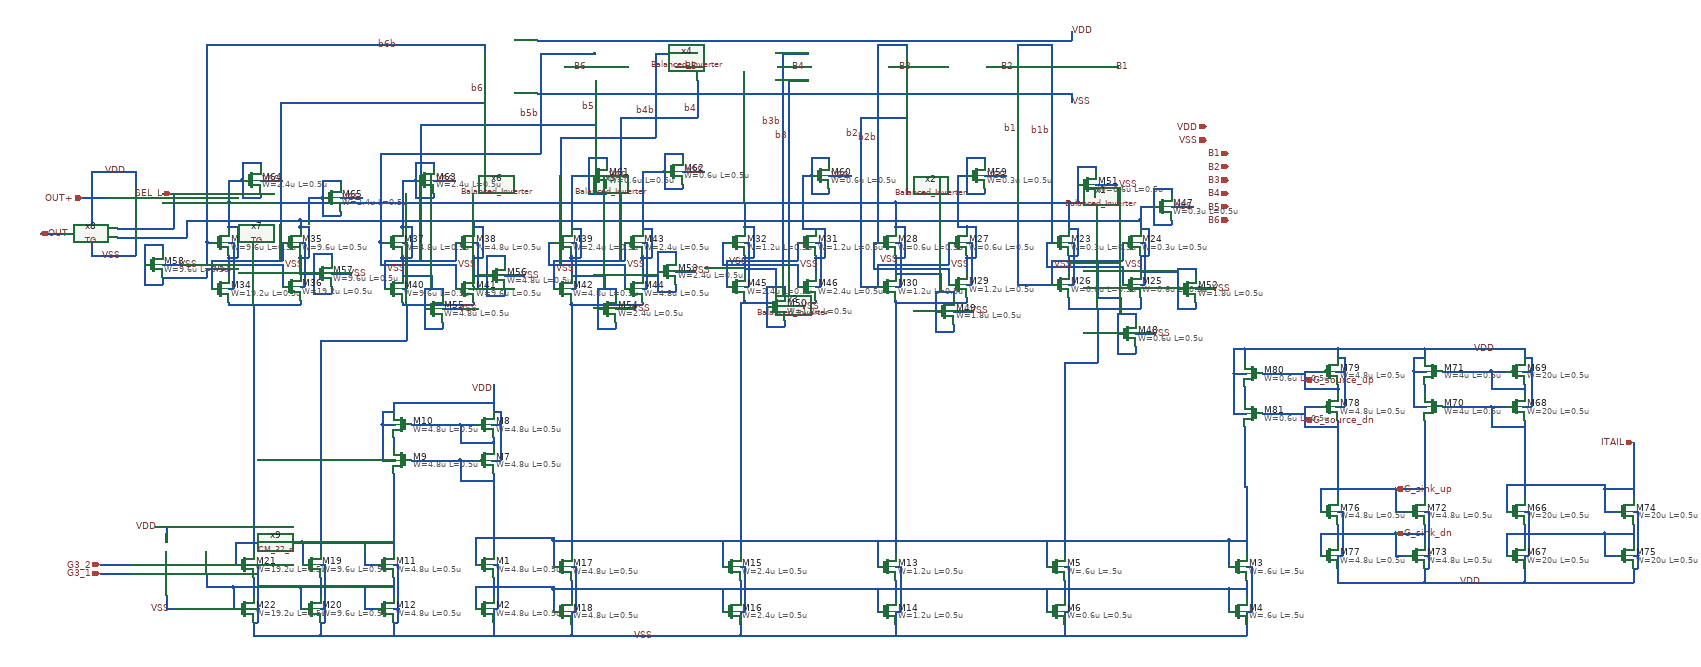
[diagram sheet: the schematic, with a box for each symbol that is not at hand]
v {xschem version=3.1.0 file_version=1.2
}
G {}
K {}
V {}
S {}
E {}
N 1940 -170 1950 -170 {
lab=VSS}
N 1950 -170 1950 -70 {
lab=VSS}
N 1940 -70 1950 -70 {
lab=VSS}
N 2350 -170 2360 -170 {
lab=VSS}
N 2360 -170 2360 -70 {
lab=VSS}
N 2350 -70 2360 -70 {
lab=VSS}
N 2310 -230 2310 -170 {
lab=#net1}
N 2310 -230 2350 -230 {
lab=#net1}
N 2310 -120 2310 -70 {
lab=#net2}
N 1940 -15 2350 -15 {
lab=VSS}
N 1560 -15 1940 -15 {
lab=VSS}
N 1210 -15 1560 -15 {
lab=VSS}
N 830 -15 1210 -15 {
lab=VSS}
N 1560 -170 1570 -170 {
lab=VSS}
N 1570 -170 1570 -70 {
lab=VSS}
N 1560 -70 1570 -70 {
lab=VSS}
N 1210 -170 1220 -170 {
lab=VSS}
N 1220 -170 1220 -70 {
lab=VSS}
N 1210 -70 1220 -70 {
lab=VSS}
N 830 -170 840 -170 {
lab=VSS}
N 840 -170 840 -70 {
lab=VSS}
N 830 -70 840 -70 {
lab=VSS}
N 1900 -230 1900 -170 {
lab=#net1}
N 1900 -120 1900 -70 {
lab=#net2}
N 1520 -230 1520 -170 {
lab=#net1}
N 1520 -120 1520 -70 {
lab=#net2}
N 1170 -230 1170 -170 {
lab=#net1}
N 1170 -120 1170 -70 {
lab=#net2}
N 790 -230 790 -170 {
lab=#net1}
N 790 -120 790 -70 {
lab=#net2}
N 2310 -120 2350 -120 {
lab=#net2}
N 2350 -270 2350 -205 {
lab=#net1}
N 2350 -70 2350 -30 {
lab=VSS}
N 1940 -70 1940 -35 {
lab=VSS}
N 1940 -35 1940 -30 {
lab=VSS}
N 1940 -30 1940 -15 {
lab=VSS}
N 2350 -30 2350 -15 {
lab=VSS}
N 1940 -135 1940 -105 {
lab=#net3}
N 2350 -135 2350 -105 {
lab=#net2}
N 1560 -135 1560 -105 {
lab=#net4}
N 1210 -135 1210 -105 {
lab=#net5}
N 830 -135 830 -105 {
lab=#net6}
N 2350 -205 2350 -200 {
lab=#net1}
N 2350 -140 2350 -135 {
lab=#net2}
N 2350 -105 2350 -100 {
lab=#net2}
N 1560 -205 1560 -200 {
lab=#net7}
N 1560 -140 1560 -135 {
lab=#net4}
N 1560 -105 1560 -100 {
lab=#net4}
N 1210 -205 1210 -200 {
lab=#net8}
N 1210 -140 1210 -135 {
lab=#net5}
N 1210 -105 1210 -100 {
lab=#net5}
N 830 -140 830 -135 {
lab=#net6}
N 830 -105 830 -100 {
lab=#net6}
N 830 -70 830 -15 {
lab=VSS}
N 1210 -70 1210 -15 {
lab=VSS}
N 1560 -70 1560 -15 {
lab=VSS}
N 1940 -140 1940 -135 {
lab=#net3}
N 1940 -105 1940 -100 {
lab=#net3}
N 790 -120 2310 -120 {
lab=#net2}
N 790 -230 2310 -230 {
lab=#net1}
N 830 -210 830 -200 {
lab=#net9}
N 655 -175 665 -175 {
lab=VSS}
N 665 -175 665 -75 {
lab=VSS}
N 655 -75 665 -75 {
lab=VSS}
N 615 -235 615 -175 {
lab=#net1}
N 615 -125 615 -75 {
lab=#net2}
N 655 -140 655 -110 {
lab=#net10}
N 655 -145 655 -140 {
lab=#net10}
N 655 -110 655 -105 {
lab=#net10}
N 655 -75 655 -20 {
lab=VSS}
N 655 -215 655 -205 {
lab=#net11}
N 655 -20 655 -15 {
lab=VSS}
N 655 -15 830 -15 {
lab=VSS}
N 790 -235 790 -230 {
lab=#net1}
N 615 -125 790 -125 {
lab=#net2}
N 790 -125 790 -120 {
lab=#net2}
N 830 -285 830 -210 {
lab=#net9}
N 1940 -295 1940 -200 {
lab=#net12}
N 1560 -210 1560 -205 {
lab=#net7}
N 1560 -320 1560 -210 {
lab=#net7}
N 1210 -345 1210 -205 {
lab=#net8}
N 655 -380 655 -215 {
lab=#net11}
N 615 -235 790 -235 {
lab=#net1}
N 580 -490 615 -490 {
lab=#net13}
N 580 -490 580 -450 {
lab=#net13}
N 580 -450 655 -450 {
lab=#net13}
N 655 -460 655 -450 {
lab=#net13}
N 655 -450 655 -440 {
lab=#net13}
N 650 -410 670 -410 {
lab=VDD}
N 670 -490 670 -410 {
lab=VDD}
N 650 -490 670 -490 {
lab=VDD}
N 670 -520 670 -490 {
lab=VDD}
N 655 -520 670 -520 {
lab=VDD}
N 655 -580 655 -520 {
lab=VDD}
N 580 -410 615 -410 {
lab=#net11}
N 580 -410 580 -365 {
lab=#net11}
N 580 -365 655 -365 {
lab=#net11}
N 470 -490 580 -490 {
lab=#net13}
N 470 -410 580 -410 {
lab=#net11}
N 430 -460 430 -440 {
lab=#net14}
N 430 -540 430 -520 {
lab=VDD}
N 430 -540 655 -540 {
lab=VDD}
N 430 -380 430 -305 {
lab=#net15}
N 405 -410 435 -410 {
lab=VDD}
N 405 -490 405 -410 {
lab=VDD}
N 405 -490 435 -490 {
lab=VDD}
N 405 -490 435 -490 {
lab=VDD}
N 405 -520 405 -490 {
lab=VDD}
N 405 -520 430 -520 {
lab=VDD}
N 430 -305 430 -205 {
lab=#net15}
N 430 -145 430 -105 {
lab=#net16}
N 430 -175 440 -175 {
lab=VSS}
N 440 -175 440 -75 {
lab=VSS}
N 430 -75 440 -75 {
lab=VSS}
N 430 -75 440 -75 {
lab=VSS}
N 440 -75 440 -45 {
lab=VSS}
N 430 -45 440 -45 {
lab=VSS}
N 430 -45 430 -15 {
lab=VSS}
N 430 -15 655 -15 {
lab=VSS}
N 265 -145 265 -105 {
lab=#net17}
N 265 -175 275 -175 {
lab=VSS}
N 275 -175 275 -75 {
lab=VSS}
N 265 -75 275 -75 {
lab=VSS}
N 265 -75 275 -75 {
lab=VSS}
N 275 -75 275 -45 {
lab=VSS}
N 265 -45 275 -45 {
lab=VSS}
N 265 -45 265 -15 {
lab=VSS}
N 225 -225 225 -175 {
lab=#net15}
N 225 -225 430 -225 {
lab=#net15}
N 365 -175 390 -175 {
lab=#net15}
N 365 -225 365 -175 {
lab=#net15}
N 365 -125 430 -125 {
lab=#net16}
N 365 -125 365 -75 {
lab=#net16}
N 365 -75 390 -75 {
lab=#net16}
N 220 -125 365 -125 {
lab=#net16}
N 220 -125 220 -75 {
lab=#net16}
N 220 -75 225 -75 {
lab=#net16}
N 265 -15 430 -15 {
lab=VSS}
N 265 -290 265 -205 {
lab=#net18}
N 115 -145 115 -105 {
lab=#net19}
N 115 -175 125 -175 {
lab=VSS}
N 125 -175 125 -75 {
lab=VSS}
N 115 -75 125 -75 {
lab=VSS}
N 115 -75 125 -75 {
lab=VSS}
N 125 -75 125 -45 {
lab=VSS}
N 115 -45 125 -45 {
lab=VSS}
N 115 -45 115 -15 {
lab=VSS}
N 75 -225 75 -175 {
lab=#net15}
N 70 -125 70 -75 {
lab=#net16}
N 70 -75 75 -75 {
lab=#net16}
N 115 -290 115 -205 {
lab=#net20}
N 70 -125 220 -125 {
lab=#net16}
N 75 -225 225 -225 {
lab=#net15}
N 115 -15 265 -15 {
lab=VSS}
N 2015 -1295 2055 -1295 {
lab=B1}
N 1705 -1355 1955 -1355 {
lab=VDD}
N 1485 -1355 1705 -1355 {
lab=VDD}
N 1235 -1355 1485 -1355 {
lab=VDD}
N 1005 -1355 1235 -1355 {
lab=VDD}
N 755 -1355 1005 -1355 {
lab=VDD}
N 755 -1235 1005 -1235 {
lab=VSS}
N 1005 -1235 1235 -1235 {
lab=VSS}
N 1235 -1235 1485 -1235 {
lab=VSS}
N 1485 -1235 1705 -1235 {
lab=VSS}
N 1705 -1235 1955 -1235 {
lab=VSS}
N 1835 -1345 1835 -1325 {
lab=b1b}
N 1835 -1265 1835 -1245 {
lab=b1}
N 1765 -1295 1795 -1295 {
lab=B2}
N 1545 -1295 1565 -1295 {
lab=B3}
N 1295 -1295 1325 -1295 {
lab=B4}
N 1065 -1295 1085 -1295 {
lab=B5}
N 885 -1265 885 -1245 {
lab=b5}
N 815 -1295 835 -1295 {
lab=B6}
N 635 -1345 635 -1325 {
lab=b6b}
N 635 -1265 635 -1245 {
lab=b6}
N 60 -990 1560 -990 {
lab=#net21}
N 1560 -990 1950 -990 {
lab=#net21}
N 1950 -990 1950 -930 {
lab=#net21}
N 2110 -950 2110 -930 {
lab=#net22}
N 180 -900 180 -860 {
lab=b6}
N 20 -860 180 -860 {
lab=b6}
N 20 -860 20 -800 {
lab=b6}
N 10 -900 20 -900 {
lab=b6b}
N 10 -900 10 -850 {
lab=b6b}
N 10 -850 180 -850 {
lab=b6b}
N 180 -850 180 -800 {
lab=b6b}
N 60 -900 70 -900 {
lab=VSS}
N 70 -900 70 -800 {
lab=VSS}
N 220 -900 230 -900 {
lab=VSS}
N 230 -900 230 -800 {
lab=VSS}
N 220 -800 230 -800 {
lab=VSS}
N 450 -900 460 -900 {
lab=VSS}
N 460 -900 460 -800 {
lab=VSS}
N 610 -900 620 -900 {
lab=VSS}
N 620 -900 620 -800 {
lab=VSS}
N 400 -900 410 -900 {
lab=b5b}
N 400 -900 400 -850 {
lab=b5b}
N 400 -850 570 -850 {
lab=b5b}
N 570 -850 570 -800 {
lab=b5b}
N 570 -900 570 -860 {
lab=b5}
N 410 -860 570 -860 {
lab=b5}
N 410 -860 410 -800 {
lab=b5}
N 780 -900 780 -850 {
lab=b4b}
N 780 -850 950 -850 {
lab=b4b}
N 950 -850 950 -800 {
lab=b4b}
N 790 -860 790 -800 {
lab=b4}
N 790 -860 950 -860 {
lab=b4}
N 950 -900 950 -860 {
lab=b4}
N 1220 -900 1230 -900 {
lab=VSS}
N 1230 -900 1230 -800 {
lab=VSS}
N 1220 -800 1230 -800 {
lab=VSS}
N 1380 -900 1390 -900 {
lab=VSS}
N 1390 -900 1390 -800 {
lab=VSS}
N 1380 -800 1390 -800 {
lab=VSS}
N 1560 -900 1570 -900 {
lab=VSS}
N 1570 -900 1570 -800 {
lab=VSS}
N 1560 -800 1570 -800 {
lab=VSS}
N 1720 -900 1730 -900 {
lab=VSS}
N 830 -760 990 -760 {
lab=#net9}
N 1220 -765 1380 -765 {
lab=#net8}
N 1170 -900 1180 -900 {
lab=b3b}
N 1170 -900 1170 -850 {
lab=b3b}
N 1170 -850 1340 -850 {
lab=b3b}
N 1340 -850 1340 -800 {
lab=b3b}
N 1340 -900 1340 -860 {
lab=b3}
N 1180 -860 1340 -860 {
lab=b3}
N 1180 -860 1180 -800 {
lab=b3}
N 1510 -900 1520 -900 {
lab=b2b}
N 1510 -900 1510 -840 {
lab=b2b}
N 1510 -840 1680 -840 {
lab=b2b}
N 1680 -900 1680 -850 {
lab=b2}
N 1520 -850 1680 -850 {
lab=b2}
N 1520 -850 1520 -800 {
lab=b2}
N 1950 -900 1960 -900 {
lab=VSS}
N 2110 -900 2120 -900 {
lab=VSS}
N 2070 -900 2070 -860 {
lab=b1}
N 1910 -860 2070 -860 {
lab=b1}
N 1900 -900 1910 -900 {
lab=b1b}
N 1900 -845 2070 -845 {
lab=b1b}
N 1210 -765 1220 -765 {
lab=#net8}
N 1955 -1375 1955 -1355 {
lab=VDD}
N 1955 -1235 1955 -1215 {
lab=VSS}
N 830 -900 840 -900 {
lab=VSS}
N 840 -900 840 -800 {
lab=VSS}
N 990 -900 1000 -900 {
lab=VSS}
N 1000 -900 1000 -800 {
lab=VSS}
N 80 -930 80 -870 {
lab=#net21}
N 220 -935 240 -935 {
lab=#net22}
N 240 -930 240 -870 {
lab=#net22}
N 470 -930 470 -870 {
lab=#net21}
N 630 -930 630 -870 {
lab=#net22}
N 850 -930 850 -870 {
lab=#net21}
N 1010 -930 1010 -870 {
lab=#net22}
N 1240 -930 1240 -870 {
lab=#net21}
N 1400 -930 1400 -870 {
lab=#net22}
N 1580 -930 1580 -870 {
lab=#net21}
N 1740 -930 1740 -870 {
lab=#net22}
N 1950 -930 1970 -930 {
lab=#net21}
N 1970 -930 1970 -870 {
lab=#net21}
N 1950 -870 1970 -870 {
lab=#net21}
N 2110 -930 2130 -930 {
lab=#net22}
N 2130 -930 2130 -870 {
lab=#net22}
N 2110 -870 2130 -870 {
lab=#net22}
N 1500 -800 1520 -800 {
lab=b2}
N 2070 -840 2070 -805 {
lab=b1b}
N 2120 -900 2120 -805 {
lab=VSS}
N 2110 -870 2110 -840 {
lab=#net22}
N 1950 -870 1950 -840 {
lab=#net21}
N 1960 -900 1960 -805 {
lab=VSS}
N 1950 -805 1960 -805 {
lab=VSS}
N 2070 -845 2070 -840 {
lab=b1b}
N 1910 -860 1910 -805 {
lab=b1}
N 1850 -805 1910 -805 {
lab=b1}
N 1720 -935 1740 -935 {
lab=#net22}
N 1740 -935 1740 -930 {
lab=#net22}
N 1720 -865 1740 -865 {
lab=#net22}
N 1740 -870 1740 -865 {
lab=#net22}
N 1560 -990 1560 -935 {
lab=#net21}
N 1560 -935 1580 -935 {
lab=#net21}
N 1580 -935 1580 -930 {
lab=#net21}
N 1560 -865 1580 -865 {
lab=#net21}
N 1580 -870 1580 -865 {
lab=#net21}
N 1720 -865 1720 -840 {
lab=#net22}
N 1730 -900 1730 -805 {
lab=VSS}
N 1720 -805 1730 -805 {
lab=VSS}
N 1680 -840 1680 -805 {
lab=b2b}
N 1560 -765 1720 -765 {
lab=#net7}
N 1720 -770 1720 -765 {
lab=#net7}
N 1560 -865 1560 -835 {
lab=#net21}
N 1380 -865 1400 -865 {
lab=#net22}
N 1400 -870 1400 -865 {
lab=#net22}
N 1220 -990 1220 -935 {
lab=#net21}
N 1240 -935 1240 -930 {
lab=#net21}
N 1220 -935 1240 -935 {
lab=#net21}
N 1220 -865 1240 -865 {
lab=#net21}
N 1240 -870 1240 -865 {
lab=#net21}
N 1380 -865 1380 -835 {
lab=#net22}
N 1220 -865 1220 -835 {
lab=#net21}
N 990 -865 990 -830 {
lab=#net22}
N 990 -865 1010 -865 {
lab=#net22}
N 1010 -870 1010 -865 {
lab=#net22}
N 990 -950 990 -935 {
lab=#net22}
N 780 -900 790 -900 {
lab=b4b}
N 830 -865 850 -865 {
lab=#net21}
N 850 -870 850 -865 {
lab=#net21}
N 830 -865 830 -830 {
lab=#net21}
N 990 -795 1000 -795 {
lab=VSS}
N 1000 -800 1000 -795 {
lab=VSS}
N 790 -800 790 -795 {
lab=b4}
N 950 -800 950 -795 {
lab=b4b}
N 830 -795 840 -795 {
lab=VSS}
N 840 -800 840 -795 {
lab=VSS}
N 610 -950 610 -935 {
lab=#net22}
N 610 -935 630 -935 {
lab=#net22}
N 630 -935 630 -930 {
lab=#net22}
N 610 -865 630 -865 {
lab=#net22}
N 630 -870 630 -865 {
lab=#net22}
N 610 -865 610 -830 {
lab=#net22}
N 450 -990 450 -935 {
lab=#net21}
N 450 -865 450 -830 {
lab=#net21}
N 470 -870 470 -865 {
lab=#net21}
N 450 -865 470 -865 {
lab=#net21}
N 470 -935 470 -930 {
lab=#net21}
N 450 -935 470 -935 {
lab=#net21}
N 620 -800 620 -795 {
lab=VSS}
N 610 -795 620 -795 {
lab=VSS}
N 570 -800 570 -795 {
lab=b5b}
N 450 -795 460 -795 {
lab=VSS}
N 460 -800 460 -795 {
lab=VSS}
N 410 -800 410 -795 {
lab=b5}
N 450 -760 610 -760 {
lab=#net18}
N 220 -950 220 -935 {
lab=#net22}
N 240 -935 240 -930 {
lab=#net22}
N 220 -865 240 -865 {
lab=#net22}
N 240 -870 240 -865 {
lab=#net22}
N 220 -865 220 -830 {
lab=#net22}
N 60 -990 60 -935 {
lab=#net21}
N 60 -935 80 -935 {
lab=#net21}
N 80 -935 80 -930 {
lab=#net21}
N 60 -865 80 -865 {
lab=#net21}
N 80 -870 80 -865 {
lab=#net21}
N 60 -865 60 -830 {
lab=#net21}
N 60 -760 220 -760 {
lab=#net20}
N 220 -765 220 -760 {
lab=#net20}
N 20 -800 20 -795 {
lab=b6}
N 60 -795 70 -795 {
lab=VSS}
N 70 -800 70 -795 {
lab=VSS}
N 2110 -805 2120 -805 {
lab=VSS}
N 2110 -840 2110 -835 {
lab=#net22}
N 1950 -840 1950 -835 {
lab=#net21}
N 1720 -935 1720 -930 {
lab=#net22}
N 1560 -935 1560 -930 {
lab=#net21}
N 1720 -870 1720 -865 {
lab=#net22}
N 1560 -870 1560 -865 {
lab=#net21}
N 1720 -840 1720 -835 {
lab=#net22}
N 1720 -775 1720 -770 {
lab=#net7}
N 1560 -835 1560 -830 {
lab=#net21}
N 1560 -770 1560 -765 {
lab=#net7}
N 1380 -870 1380 -865 {
lab=#net22}
N 1220 -935 1220 -930 {
lab=#net21}
N 1220 -870 1220 -865 {
lab=#net21}
N 60 -935 60 -930 {
lab=#net21}
N 60 -870 60 -865 {
lab=#net21}
N 60 -830 60 -825 {
lab=#net21}
N 60 -765 60 -760 {
lab=#net20}
N 220 -935 220 -930 {
lab=#net22}
N 220 -870 220 -865 {
lab=#net22}
N 220 -835 220 -830 {
lab=#net22}
N 220 -770 220 -765 {
lab=#net20}
N 450 -935 450 -930 {
lab=#net21}
N 450 -870 450 -865 {
lab=#net21}
N 610 -935 610 -930 {
lab=#net22}
N 610 -870 610 -865 {
lab=#net22}
N 830 -870 830 -865 {
lab=#net21}
N 450 -830 450 -825 {
lab=#net21}
N 450 -765 450 -760 {
lab=#net18}
N 610 -830 610 -825 {
lab=#net22}
N 610 -765 610 -760 {
lab=#net18}
N 830 -830 830 -825 {
lab=#net21}
N 830 -765 830 -760 {
lab=#net9}
N 990 -935 990 -930 {
lab=#net22}
N 990 -870 990 -865 {
lab=#net22}
N 990 -830 990 -825 {
lab=#net22}
N 990 -765 990 -760 {
lab=#net9}
N 1220 -835 1220 -830 {
lab=#net21}
N 1220 -770 1220 -765 {
lab=#net8}
N 1380 -835 1380 -830 {
lab=#net22}
N 1380 -770 1380 -765 {
lab=#net8}
N 1950 -775 1950 -750 {
lab=#net12}
N 1950 -750 2110 -750 {
lab=#net12}
N 2110 -775 2110 -750 {
lab=#net12}
N 2015 -750 2015 -630 {
lab=#net12}
N 1940 -630 2015 -630 {
lab=#net12}
N 2140 -1020 2140 -980 {
lab=#net22}
N 2140 -1020 2180 -1020 {
lab=#net22}
N 2180 -1020 2180 -1010 {
lab=#net22}
N 2180 -950 2180 -940 {
lab=#net22}
N 2140 -940 2180 -940 {
lab=#net22}
N 2140 -980 2140 -940 {
lab=#net22}
N 2180 -980 2230 -980 {
lab=VSS}
N 2110 -980 2110 -950 {
lab=#net22}
N 2110 -980 2140 -980 {
lab=#net22}
N 2060 -740 2060 -695 {
lab=#net21}
N 2060 -740 2100 -740 {
lab=#net21}
N 2100 -740 2100 -725 {
lab=#net21}
N 2060 -695 2060 -650 {
lab=#net21}
N 2060 -650 2100 -650 {
lab=#net21}
N 2100 -665 2100 -650 {
lab=#net21}
N 2100 -695 2145 -695 {
lab=VSS}
N 2065 -775 2065 -740 {
lab=#net21}
N 2015 -775 2065 -775 {
lab=#net21}
N 2015 -855 2015 -775 {
lab=#net21}
N 1950 -855 2015 -855 {
lab=#net21}
N 1650 -790 1650 -745 {
lab=#net21}
N 1650 -790 1690 -790 {
lab=#net21}
N 1690 -790 1690 -775 {
lab=#net21}
N 1650 -745 1650 -700 {
lab=#net21}
N 1650 -700 1690 -700 {
lab=#net21}
N 1690 -715 1690 -700 {
lab=#net21}
N 1690 -745 1735 -745 {
lab=VSS}
N 1560 -830 1660 -830 {
lab=#net21}
N 1660 -830 1660 -790 {
lab=#net21}
N 1270 -800 1270 -755 {
lab=#net21}
N 1270 -800 1310 -800 {
lab=#net21}
N 1310 -800 1310 -785 {
lab=#net21}
N 1270 -755 1270 -710 {
lab=#net21}
N 1270 -710 1310 -710 {
lab=#net21}
N 1310 -725 1310 -710 {
lab=#net21}
N 1310 -755 1355 -755 {
lab=VSS}
N 1220 -840 1290 -840 {
lab=#net21}
N 1290 -840 1290 -800 {
lab=#net21}
N 1970 -1070 1970 -1030 {
lab=#net21}
N 1970 -1070 2010 -1070 {
lab=#net21}
N 2010 -1070 2010 -1060 {
lab=#net21}
N 2010 -1000 2010 -990 {
lab=#net21}
N 1970 -990 2010 -990 {
lab=#net21}
N 1970 -1030 1970 -990 {
lab=#net21}
N 2010 -1030 2060 -1030 {
lab=VSS}
N 1950 -990 1970 -990 {
lab=#net21}
N 2195 -840 2195 -795 {
lab=#net22}
N 2195 -840 2235 -840 {
lab=#net22}
N 2235 -840 2235 -825 {
lab=#net22}
N 2195 -795 2195 -750 {
lab=#net22}
N 2195 -750 2235 -750 {
lab=#net22}
N 2235 -765 2235 -750 {
lab=#net22}
N 2235 -795 2280 -795 {
lab=VSS}
N 2110 -835 2195 -835 {
lab=#net22}
N 1025 -880 1025 -835 {
lab=#net22}
N 1025 -880 1065 -880 {
lab=#net22}
N 1065 -880 1065 -865 {
lab=#net22}
N 1025 -835 1025 -790 {
lab=#net22}
N 1025 -790 1065 -790 {
lab=#net22}
N 1065 -805 1065 -790 {
lab=#net22}
N 1065 -835 1110 -835 {
lab=VSS}
N 990 -825 1025 -825 {
lab=#net22}
N 890 -795 890 -750 {
lab=#net21}
N 890 -795 930 -795 {
lab=#net21}
N 930 -795 930 -780 {
lab=#net21}
N 890 -750 890 -705 {
lab=#net21}
N 890 -705 930 -705 {
lab=#net21}
N 930 -720 930 -705 {
lab=#net21}
N 930 -750 975 -750 {
lab=VSS}
N 830 -825 905 -825 {
lab=#net21}
N 905 -825 905 -795 {
lab=#net21}
N 600 -795 610 -795 {
lab=VSS}
N 610 -800 610 -795 {
lab=VSS}
N 500 -795 500 -750 {
lab=#net21}
N 500 -795 540 -795 {
lab=#net21}
N 540 -795 540 -780 {
lab=#net21}
N 500 -750 500 -705 {
lab=#net21}
N 500 -705 540 -705 {
lab=#net21}
N 540 -720 540 -705 {
lab=#net21}
N 540 -750 585 -750 {
lab=VSS}
N 450 -825 515 -825 {
lab=#net21}
N 515 -825 515 -795 {
lab=#net21}
N 640 -870 640 -825 {
lab=#net22}
N 640 -870 680 -870 {
lab=#net22}
N 680 -870 680 -855 {
lab=#net22}
N 640 -825 640 -780 {
lab=#net22}
N 640 -780 680 -780 {
lab=#net22}
N 680 -795 680 -780 {
lab=#net22}
N 680 -825 725 -825 {
lab=VSS}
N 610 -825 640 -825 {
lab=#net22}
N 250 -875 250 -830 {
lab=#net22}
N 250 -875 290 -875 {
lab=#net22}
N 290 -875 290 -860 {
lab=#net22}
N 250 -830 250 -785 {
lab=#net22}
N 250 -785 290 -785 {
lab=#net22}
N 290 -800 290 -785 {
lab=#net22}
N 290 -830 335 -830 {
lab=VSS}
N 220 -830 250 -830 {
lab=#net22}
N -130 -895 -130 -850 {
lab=#net21}
N -130 -895 -90 -895 {
lab=#net21}
N -90 -895 -90 -880 {
lab=#net21}
N -130 -850 -130 -805 {
lab=#net21}
N -130 -805 -90 -805 {
lab=#net21}
N -90 -820 -90 -805 {
lab=#net21}
N -90 -850 -45 -850 {
lab=VSS}
N -90 -820 10 -820 {
lab=#net21}
N 10 -840 10 -820 {
lab=#net21}
N 10 -840 60 -840 {
lab=#net21}
N 1720 -1090 1720 -1050 {
lab=#net22}
N 1720 -1090 1760 -1090 {
lab=#net22}
N 1760 -1090 1760 -1080 {
lab=#net22}
N 1760 -1020 1760 -1010 {
lab=#net22}
N 1720 -1010 1760 -1010 {
lab=#net22}
N 1720 -1050 1720 -1010 {
lab=#net22}
N 1760 -1050 1810 -1050 {
lab=VSS}
N 1700 -1050 1700 -950 {
lab=#net22}
N 1700 -1050 1720 -1050 {
lab=#net22}
N 1370 -1090 1370 -1050 {
lab=#net22}
N 1370 -1090 1410 -1090 {
lab=#net22}
N 1410 -1090 1410 -1080 {
lab=#net22}
N 1410 -1020 1410 -1010 {
lab=#net22}
N 1370 -1010 1410 -1010 {
lab=#net22}
N 1370 -1050 1370 -1010 {
lab=#net22}
N 1410 -1050 1460 -1050 {
lab=VSS}
N 1350 -1050 1370 -1050 {
lab=#net22}
N 1350 -1050 1350 -950 {
lab=#net22}
N 870 -1090 870 -1050 {
lab=#net21}
N 870 -1090 910 -1090 {
lab=#net21}
N 910 -1090 910 -1080 {
lab=#net21}
N 910 -1020 910 -1010 {
lab=#net21}
N 870 -1010 910 -1010 {
lab=#net21}
N 870 -1050 870 -1010 {
lab=#net21}
N 910 -1050 960 -1050 {
lab=VSS}
N 850 -1050 870 -1050 {
lab=#net21}
N 830 -1050 850 -1050 {
lab=#net21}
N 1040 -1100 1040 -1060 {
lab=#net22}
N 1040 -1100 1080 -1100 {
lab=#net22}
N 1080 -1100 1080 -1090 {
lab=#net22}
N 1080 -1030 1080 -1020 {
lab=#net22}
N 1040 -1020 1080 -1020 {
lab=#net22}
N 1040 -1060 1040 -1020 {
lab=#net22}
N 1080 -1060 1130 -1060 {
lab=VSS}
N 1020 -1060 1040 -1060 {
lab=#net22}
N 480 -1080 480 -1040 {
lab=#net21}
N 480 -1080 520 -1080 {
lab=#net21}
N 520 -1080 520 -1070 {
lab=#net21}
N 520 -1010 520 -1000 {
lab=#net21}
N 480 -1000 520 -1000 {
lab=#net21}
N 480 -1040 480 -1000 {
lab=#net21}
N 520 -1040 570 -1040 {
lab=VSS}
N 460 -1040 480 -1040 {
lab=#net21}
N 450 -1040 460 -1040 {
lab=#net21}
N 450 -1040 450 -990 {
lab=#net21}
N 90 -1080 90 -1040 {
lab=#net21}
N 90 -1080 130 -1080 {
lab=#net21}
N 130 -1080 130 -1070 {
lab=#net21}
N 130 -1010 130 -1000 {
lab=#net21}
N 90 -1000 130 -1000 {
lab=#net21}
N 90 -1040 90 -1000 {
lab=#net21}
N 130 -1040 180 -1040 {
lab=VSS}
N 70 -1040 90 -1040 {
lab=#net21}
N 60 -1040 70 -1040 {
lab=#net21}
N 60 -1040 60 -990 {
lab=#net21}
N 270 -1040 270 -1000 {
lab=#net22}
N 270 -1040 310 -1040 {
lab=#net22}
N 310 -1040 310 -1030 {
lab=#net22}
N 310 -970 310 -960 {
lab=#net22}
N 270 -960 310 -960 {
lab=#net22}
N 270 -1000 270 -960 {
lab=#net22}
N 310 -1000 360 -1000 {
lab=VSS}
N 250 -1000 270 -1000 {
lab=#net22}
N 240 -1000 250 -1000 {
lab=#net22}
N 240 -1000 240 -950 {
lab=#net22}
N 1835 -1245 1835 -805 {
lab=b1}
N 1835 -805 1850 -805 {
lab=b1}
N 1900 -900 1900 -845 {
lab=b1b}
N 1835 -1345 1910 -1345 {
lab=b1b}
N 1910 -1345 1910 -905 {
lab=b1b}
N 1910 -905 1910 -900 {
lab=b1b}
N 1585 -1265 1585 -1180 {
lab=b2}
N 1480 -1180 1585 -1180 {
lab=b2}
N 1480 -1180 1480 -800 {
lab=b2}
N 1480 -800 1500 -800 {
lab=b2}
N 1585 -1345 1585 -1325 {
lab=b2b}
N 1520 -1345 1520 -900 {
lab=b2b}
N 1520 -1345 1585 -1345 {
lab=b2b}
N 1320 -1265 1320 -860 {
lab=b3}
N 1320 -1265 1365 -1265 {
lab=b3}
N 1305 -1325 1305 -850 {
lab=b3b}
N 1305 -1325 1365 -1325 {
lab=b3b}
N 1115 -1265 1115 -1180 {
lab=b4}
N 1030 -1180 1115 -1180 {
lab=b4}
N 985 -1180 1030 -1180 {
lab=b4}
N 940 -1180 985 -1180 {
lab=b4}
N 940 -1180 940 -860 {
lab=b4}
N 1020 -1325 1115 -1325 {
lab=b4b}
N 1020 -1325 1020 -1135 {
lab=b4b}
N 805 -1135 1020 -1135 {
lab=b4b}
N 805 -1135 805 -850 {
lab=b4b}
N 885 -1245 885 -1205 {
lab=b5}
N 885 -1205 885 -1165 {
lab=b5}
N 570 -1165 885 -1165 {
lab=b5}
N 490 -1165 490 -860 {
lab=b5}
N 490 -1165 570 -1165 {
lab=b5}
N 760 -1325 885 -1325 {
lab=b5b}
N 760 -1325 760 -1100 {
lab=b5b}
N 400 -1100 760 -1100 {
lab=b5b}
N 400 -1100 400 -900 {
lab=b5b}
N 635 -1245 635 -1215 {
lab=b6}
N 195 -1215 635 -1215 {
lab=b6}
N 175 -1215 195 -1215 {
lab=b6}
N 175 -1215 175 -860 {
lab=b6}
N 10 -1345 635 -1345 {
lab=b6b}
N 10 -1345 10 -900 {
lab=b6b}
N 1700 -950 1700 -935 {
lab=#net22}
N 1700 -935 1720 -935 {
lab=#net22}
N 1350 -950 1350 -930 {
lab=#net22}
N 1350 -930 1380 -930 {
lab=#net22}
N 1380 -930 1400 -930 {
lab=#net22}
N 990 -1060 1020 -1060 {
lab=#net22}
N 990 -1060 990 -950 {
lab=#net22}
N 990 -930 1010 -930 {
lab=#net22}
N 830 -930 850 -930 {
lab=#net21}
N 220 -950 2110 -950 {
lab=#net22}
N 830 -1050 830 -990 {
lab=#net21}
N 830 -990 830 -930 {
lab=#net21}
N 1940 -630 1940 -295 {
lab=#net12}
N 1560 -765 1560 -320 {
lab=#net7}
N 1210 -765 1210 -345 {
lab=#net8}
N 830 -760 830 -285 {
lab=#net9}
N 265 -680 265 -290 {
lab=#net18}
N 265 -680 460 -680 {
lab=#net18}
N 460 -760 460 -680 {
lab=#net18}
N 115 -760 115 -290 {
lab=#net20}
N -150 -1060 -150 -1020 {
lab=VDD}
N -180 -1060 -150 -1060 {
lab=VDD}
N -150 -980 -150 -870 {
lab=VSS}
N -250 -870 -150 -870 {
lab=VSS}
N -250 -900 -250 -870 {
lab=VSS}
N -90 -990 60 -990 {
lab=#net21}
N -270 -1000 -210 -1000 {
lab=OUT+}
N -350 -920 -310 -920 {
lab=OUT-}
N -365 -920 -350 -920 {
lab=OUT-}
N -250 -1060 -250 -940 {
lab=VDD}
N -250 -1060 -180 -1060 {
lab=VDD}
N -190 -930 -90 -930 {
lab=SEL_L}
N -90 -930 -65 -930 {
lab=SEL_L}
N -65 -1010 -65 -930 {
lab=SEL_L}
N -90 -1010 -65 -1010 {
lab=SEL_L}
N 10 -175 75 -175 {
lab=#net15}
N 10 -125 70 -125 {
lab=#net16}
N 10 -155 10 -125 {
lab=#net16}
N -230 -175 -160 -175 {
lab=G3_2}
N -230 -155 -160 -155 {
lab=G3_1}
N -80 -260 -80 -225 {
lab=VDD}
N -105 -260 -80 -260 {
lab=VDD}
N -80 -105 -80 -75 {
lab=VSS}
N -80 -75 -60 -75 {
lab=VSS}
N -35 -950 220 -950 {
lab=#net22}
N -35 -950 -35 -910 {
lab=#net22}
N -190 -910 -35 -910 {
lab=#net22}
N 2975 -295 2985 -295 {
lab=VDD}
N 2985 -295 2985 -195 {
lab=VDD}
N 2975 -195 2985 -195 {
lab=VDD}
N 2975 -260 2975 -230 {
lab=#net23}
N 2975 -265 2975 -260 {
lab=#net23}
N 2975 -230 2975 -225 {
lab=#net23}
N 2975 -195 2975 -140 {
lab=VDD}
N 2975 -335 2975 -325 {
lab=#net24}
N 2975 -140 2975 -135 {
lab=VDD}
N 2975 -500 2975 -335 {
lab=#net24}
N 2900 -610 2935 -610 {
lab=#net25}
N 2900 -610 2900 -570 {
lab=#net25}
N 2900 -570 2975 -570 {
lab=#net25}
N 2975 -580 2975 -570 {
lab=#net25}
N 2975 -570 2975 -560 {
lab=#net25}
N 2970 -530 2990 -530 {
lab=VDD}
N 2990 -610 2990 -530 {
lab=VDD}
N 2970 -610 2990 -610 {
lab=VDD}
N 2990 -640 2990 -610 {
lab=VDD}
N 2975 -640 2990 -640 {
lab=VDD}
N 2900 -530 2935 -530 {
lab=#net24}
N 2900 -530 2900 -485 {
lab=#net24}
N 2900 -485 2975 -485 {
lab=#net24}
N 2790 -610 2900 -610 {
lab=#net25}
N 2790 -530 2900 -530 {
lab=#net24}
N 2750 -580 2750 -560 {
lab=#net26}
N 2750 -660 2750 -640 {
lab=VDD}
N 2750 -660 2975 -660 {
lab=VDD}
N 2750 -500 2750 -425 {
lab=G_sink_up}
N 2725 -530 2755 -530 {
lab=VDD}
N 2725 -610 2725 -530 {
lab=VDD}
N 2725 -610 2755 -610 {
lab=VDD}
N 2725 -610 2755 -610 {
lab=VDD}
N 2725 -640 2725 -610 {
lab=VDD}
N 2725 -640 2750 -640 {
lab=VDD}
N 2750 -425 2750 -325 {
lab=G_sink_up}
N 2750 -265 2750 -225 {
lab=G_sink_dn}
N 2750 -295 2760 -295 {
lab=VDD}
N 2760 -295 2760 -195 {
lab=VDD}
N 2750 -195 2760 -195 {
lab=VDD}
N 2750 -195 2760 -195 {
lab=VDD}
N 2760 -195 2760 -165 {
lab=VDD}
N 2750 -165 2760 -165 {
lab=VDD}
N 2750 -165 2750 -135 {
lab=VDD}
N 2750 -135 2975 -135 {
lab=VSS}
N 2685 -295 2710 -295 {
lab=G_sink_up}
N 2685 -345 2685 -295 {
lab=G_sink_up}
N 2685 -245 2750 -245 {
lab=G_sink_dn}
N 2685 -245 2685 -195 {
lab=G_sink_dn}
N 2685 -195 2710 -195 {
lab=G_sink_dn}
N 2685 -345 2750 -345 {
lab=G_sink_up}
N 2935 -355 2935 -295 {
lab=ITAIL}
N 2935 -355 3155 -355 {
lab=ITAIL}
N 2935 -245 2935 -195 {
lab=#net27}
N 2935 -245 3150 -245 {
lab=#net27}
N 3220 -265 3220 -225 {
lab=#net27}
N 3220 -295 3230 -295 {
lab=VDD}
N 3230 -295 3230 -195 {
lab=VDD}
N 3220 -195 3230 -195 {
lab=VDD}
N 3220 -195 3230 -195 {
lab=VDD}
N 3230 -195 3230 -165 {
lab=VDD}
N 3220 -165 3230 -165 {
lab=VDD}
N 3220 -165 3220 -135 {
lab=VDD}
N 3155 -295 3180 -295 {
lab=ITAIL}
N 3155 -345 3155 -295 {
lab=ITAIL}
N 3155 -245 3220 -245 {
lab=#net27}
N 3155 -245 3155 -195 {
lab=#net27}
N 3155 -195 3180 -195 {
lab=#net27}
N 3155 -345 3220 -345 {
lab=ITAIL}
N 3150 -245 3155 -245 {
lab=#net27}
N 3155 -355 3155 -345 {
lab=ITAIL}
N 3220 -345 3220 -325 {
lab=ITAIL}
N 2975 -135 3220 -135 {
lab=VDD}
N 3220 -450 3220 -345 {
lab=ITAIL}
N 2555 -295 2565 -295 {
lab=VDD}
N 2565 -295 2565 -195 {
lab=VDD}
N 2555 -195 2565 -195 {
lab=VDD}
N 2555 -260 2555 -230 {
lab=#net28}
N 2555 -265 2555 -260 {
lab=#net28}
N 2555 -230 2555 -225 {
lab=#net28}
N 2555 -335 2555 -325 {
lab=G_source_dn}
N 2555 -500 2555 -335 {
lab=G_source_dn}
N 2480 -610 2515 -610 {
lab=G_source_up}
N 2480 -610 2480 -570 {
lab=G_source_up}
N 2480 -570 2555 -570 {
lab=G_source_up}
N 2555 -580 2555 -570 {
lab=G_source_up}
N 2555 -570 2555 -560 {
lab=G_source_up}
N 2550 -530 2570 -530 {
lab=VDD}
N 2570 -610 2570 -530 {
lab=VDD}
N 2550 -610 2570 -610 {
lab=VDD}
N 2570 -640 2570 -610 {
lab=VDD}
N 2555 -640 2570 -640 {
lab=VDD}
N 2480 -530 2515 -530 {
lab=G_source_dn}
N 2480 -530 2480 -485 {
lab=G_source_dn}
N 2480 -485 2555 -485 {
lab=G_source_dn}
N 2515 -245 2515 -195 {
lab=G_sink_dn}
N 2555 -165 2555 -135 {
lab=VDD}
N 2555 -135 2750 -135 {
lab=VDD}
N 2555 -195 2555 -165 {
lab=VDD}
N 2555 -660 2750 -660 {
lab=VDD}
N 2555 -660 2555 -640 {
lab=VDD}
N 2515 -345 2685 -345 {
lab=G_sink_up}
N 2515 -345 2515 -295 {
lab=G_sink_up}
N 2515 -245 2685 -245 {
lab=G_sink_dn}
N 2345 -575 2345 -545 {
lab=#net29}
N 2345 -655 2345 -635 {
lab=VDD}
N 2345 -660 2345 -655 {
lab=VDD}
N 2345 -660 2555 -660 {
lab=VDD}
N 2385 -605 2480 -605 {
lab=G_source_up}
N 2385 -515 2480 -515 {
lab=G_source_dn}
N 2320 -515 2350 -515 {
lab=VDD}
N 2320 -605 2320 -515 {
lab=VDD}
N 2320 -605 2350 -605 {
lab=VDD}
N 2320 -660 2320 -605 {
lab=VDD}
N 2320 -660 2345 -660 {
lab=VDD}
N 2345 -485 2345 -435 {
lab=#net1}
N 2345 -435 2345 -350 {
lab=#net1}
N 2350 -350 2350 -270 {
lab=#net1}
N 2345 -350 2350 -350 {
lab=#net1}
N 2975 -660 2975 -640 {
lab=VDD}
C {symbols/nfet_03v3.sym} 2330 -170 0 0 {name=M3
L=.5u
W=.6u
nf=1
m=1
ad="'int((nf+1)/2) * W/nf * 0.18u'"
pd="'2*int((nf+1)/2) * (W/nf + 0.18u)'"
as="'int((nf+2)/2) * W/nf * 0.18u'"
ps="'2*int((nf+2)/2) * (W/nf + 0.18u)'"
nrd="'0.18u / W'" nrs="'0.18u / W'"
sa=0 sb=0 sd=0
model=nfet_03v3
spiceprefix=X
}
C {symbols/nfet_03v3.sym} 2330 -70 0 0 {name=M4
L=.5u
W=.6u
nf=1
m=1
ad="'int((nf+1)/2) * W/nf * 0.18u'"
pd="'2*int((nf+1)/2) * (W/nf + 0.18u)'"
as="'int((nf+2)/2) * W/nf * 0.18u'"
ps="'2*int((nf+2)/2) * (W/nf + 0.18u)'"
nrd="'0.18u / W'" nrs="'0.18u / W'"
sa=0 sb=0 sd=0
model=nfet_03v3
spiceprefix=X
}
C {symbols/nfet_03v3.sym} 1920 -170 0 0 {name=M5
L=.5u
W=.6u
nf=1
m=1
ad="'int((nf+1)/2) * W/nf * 0.18u'"
pd="'2*int((nf+1)/2) * (W/nf + 0.18u)'"
as="'int((nf+2)/2) * W/nf * 0.18u'"
ps="'2*int((nf+2)/2) * (W/nf + 0.18u)'"
nrd="'0.18u / W'" nrs="'0.18u / W'"
sa=0 sb=0 sd=0
model=nfet_03v3
spiceprefix=X
}
C {symbols/nfet_03v3.sym} 1920 -70 0 0 {name=M6
L=0.5u
W=0.6u
nf=1
m=1
ad="'int((nf+1)/2) * W/nf * 0.18u'"
pd="'2*int((nf+1)/2) * (W/nf + 0.18u)'"
as="'int((nf+2)/2) * W/nf * 0.18u'"
ps="'2*int((nf+2)/2) * (W/nf + 0.18u)'"
nrd="'0.18u / W'" nrs="'0.18u / W'"
sa=0 sb=0 sd=0
model=nfet_03v3
spiceprefix=X
}
C {symbols/nfet_03v3.sym} 1540 -170 0 0 {name=M13
L=0.5u
W=1.2u
nf=1
m=1
ad="'int((nf+1)/2) * W/nf * 0.18u'"
pd="'2*int((nf+1)/2) * (W/nf + 0.18u)'"
as="'int((nf+2)/2) * W/nf * 0.18u'"
ps="'2*int((nf+2)/2) * (W/nf + 0.18u)'"
nrd="'0.18u / W'" nrs="'0.18u / W'"
sa=0 sb=0 sd=0
model=nfet_03v3
spiceprefix=X
}
C {symbols/nfet_03v3.sym} 1540 -70 0 0 {name=M14
L=0.5u
W=1.2u
nf=1
m=1
ad="'int((nf+1)/2) * W/nf * 0.18u'"
pd="'2*int((nf+1)/2) * (W/nf + 0.18u)'"
as="'int((nf+2)/2) * W/nf * 0.18u'"
ps="'2*int((nf+2)/2) * (W/nf + 0.18u)'"
nrd="'0.18u / W'" nrs="'0.18u / W'"
sa=0 sb=0 sd=0
model=nfet_03v3
spiceprefix=X
}
C {symbols/nfet_03v3.sym} 1190 -170 0 0 {name=M15
L=0.5u
W=2.4u
nf=1
m=1
ad="'int((nf+1)/2) * W/nf * 0.18u'"
pd="'2*int((nf+1)/2) * (W/nf + 0.18u)'"
as="'int((nf+2)/2) * W/nf * 0.18u'"
ps="'2*int((nf+2)/2) * (W/nf + 0.18u)'"
nrd="'0.18u / W'" nrs="'0.18u / W'"
sa=0 sb=0 sd=0
model=nfet_03v3
spiceprefix=X
}
C {symbols/nfet_03v3.sym} 1190 -70 0 0 {name=M16
L=0.5u
W=2.4u
nf=1
m=1
ad="'int((nf+1)/2) * W/nf * 0.18u'"
pd="'2*int((nf+1)/2) * (W/nf + 0.18u)'"
as="'int((nf+2)/2) * W/nf * 0.18u'"
ps="'2*int((nf+2)/2) * (W/nf + 0.18u)'"
nrd="'0.18u / W'" nrs="'0.18u / W'"
sa=0 sb=0 sd=0
model=nfet_03v3
spiceprefix=X
}
C {symbols/nfet_03v3.sym} 810 -170 0 0 {name=M17
L=0.5u
W=4.8u
nf=1
m=1
ad="'int((nf+1)/2) * W/nf * 0.18u'"
pd="'2*int((nf+1)/2) * (W/nf + 0.18u)'"
as="'int((nf+2)/2) * W/nf * 0.18u'"
ps="'2*int((nf+2)/2) * (W/nf + 0.18u)'"
nrd="'0.18u / W'" nrs="'0.18u / W'"
sa=0 sb=0 sd=0
model=nfet_03v3
spiceprefix=X
}
C {symbols/nfet_03v3.sym} 810 -70 0 0 {name=M18
L=0.5u
W=4.8u
nf=1
m=1
ad="'int((nf+1)/2) * W/nf * 0.18u'"
pd="'2*int((nf+1)/2) * (W/nf + 0.18u)'"
as="'int((nf+2)/2) * W/nf * 0.18u'"
ps="'2*int((nf+2)/2) * (W/nf + 0.18u)'"
nrd="'0.18u / W'" nrs="'0.18u / W'"
sa=0 sb=0 sd=0
model=nfet_03v3
spiceprefix=X
}
C {symbols/nfet_03v3.sym} 635 -175 0 0 {name=M1
L=0.5u
W=4.8u
nf=1
m=1
ad="'int((nf+1)/2) * W/nf * 0.18u'"
pd="'2*int((nf+1)/2) * (W/nf + 0.18u)'"
as="'int((nf+2)/2) * W/nf * 0.18u'"
ps="'2*int((nf+2)/2) * (W/nf + 0.18u)'"
nrd="'0.18u / W'" nrs="'0.18u / W'"
sa=0 sb=0 sd=0
model=nfet_03v3
spiceprefix=X
}
C {symbols/nfet_03v3.sym} 635 -75 0 0 {name=M2
L=0.5u
W=4.8u
nf=1
m=1
ad="'int((nf+1)/2) * W/nf * 0.18u'"
pd="'2*int((nf+1)/2) * (W/nf + 0.18u)'"
as="'int((nf+2)/2) * W/nf * 0.18u'"
ps="'2*int((nf+2)/2) * (W/nf + 0.18u)'"
nrd="'0.18u / W'" nrs="'0.18u / W'"
sa=0 sb=0 sd=0
model=nfet_03v3
spiceprefix=X
}
C {symbols/pfet_03v3.sym} 635 -410 0 0 {name=M7
L=0.5u
W=4.8u
nf=1
m=1
ad="'int((nf+1)/2) * W/nf * 0.18u'"
pd="'2*int((nf+1)/2) * (W/nf + 0.18u)'"
as="'int((nf+2)/2) * W/nf * 0.18u'"
ps="'2*int((nf+2)/2) * (W/nf + 0.18u)'"
nrd="'0.18u / W'" nrs="'0.18u / W'"
sa=0 sb=0 sd=0
model=pfet_03v3
spiceprefix=X
}
C {symbols/pfet_03v3.sym} 635 -490 0 0 {name=M8
L=0.5u
W=4.8u
nf=1
m=1
ad="'int((nf+1)/2) * W/nf * 0.18u'"
pd="'2*int((nf+1)/2) * (W/nf + 0.18u)'"
as="'int((nf+2)/2) * W/nf * 0.18u'"
ps="'2*int((nf+2)/2) * (W/nf + 0.18u)'"
nrd="'0.18u / W'" nrs="'0.18u / W'"
sa=0 sb=0 sd=0
model=pfet_03v3
spiceprefix=X
}
C {symbols/pfet_03v3.sym} 450 -410 0 1 {name=M9
L=0.5u
W=4.8u
nf=1
m=1
ad="'int((nf+1)/2) * W/nf * 0.18u'"
pd="'2*int((nf+1)/2) * (W/nf + 0.18u)'"
as="'int((nf+2)/2) * W/nf * 0.18u'"
ps="'2*int((nf+2)/2) * (W/nf + 0.18u)'"
nrd="'0.18u / W'" nrs="'0.18u / W'"
sa=0 sb=0 sd=0
model=pfet_03v3
spiceprefix=X
}
C {symbols/pfet_03v3.sym} 450 -490 0 1 {name=M10
L=0.5u
W=4.8u
nf=1
m=1
ad="'int((nf+1)/2) * W/nf * 0.18u'"
pd="'2*int((nf+1)/2) * (W/nf + 0.18u)'"
as="'int((nf+2)/2) * W/nf * 0.18u'"
ps="'2*int((nf+2)/2) * (W/nf + 0.18u)'"
nrd="'0.18u / W'" nrs="'0.18u / W'"
sa=0 sb=0 sd=0
model=pfet_03v3
spiceprefix=X
}
C {symbols/nfet_03v3.sym} 410 -175 0 0 {name=M11
L=0.5u
W=4.8u
nf=1
m=1
ad="'int((nf+1)/2) * W/nf * 0.18u'"
pd="'2*int((nf+1)/2) * (W/nf + 0.18u)'"
as="'int((nf+2)/2) * W/nf * 0.18u'"
ps="'2*int((nf+2)/2) * (W/nf + 0.18u)'"
nrd="'0.18u / W'" nrs="'0.18u / W'"
sa=0 sb=0 sd=0
model=nfet_03v3
spiceprefix=X
}
C {symbols/nfet_03v3.sym} 410 -75 0 0 {name=M12
L=0.5u
W=4.8u
nf=1
m=1
ad="'int((nf+1)/2) * W/nf * 0.18u'"
pd="'2*int((nf+1)/2) * (W/nf + 0.18u)'"
as="'int((nf+2)/2) * W/nf * 0.18u'"
ps="'2*int((nf+2)/2) * (W/nf + 0.18u)'"
nrd="'0.18u / W'" nrs="'0.18u / W'"
sa=0 sb=0 sd=0
model=nfet_03v3
spiceprefix=X
}
C {symbols/nfet_03v3.sym} 245 -175 0 0 {name=M19
L=0.5u
W=9.6u
nf=1
m=1
ad="'int((nf+1)/2) * W/nf * 0.18u'"
pd="'2*int((nf+1)/2) * (W/nf + 0.18u)'"
as="'int((nf+2)/2) * W/nf * 0.18u'"
ps="'2*int((nf+2)/2) * (W/nf + 0.18u)'"
nrd="'0.18u / W'" nrs="'0.18u / W'"
sa=0 sb=0 sd=0
model=nfet_03v3
spiceprefix=X
}
C {symbols/nfet_03v3.sym} 245 -75 0 0 {name=M20
L=0.5u
W=9.6u
nf=1
m=1
ad="'int((nf+1)/2) * W/nf * 0.18u'"
pd="'2*int((nf+1)/2) * (W/nf + 0.18u)'"
as="'int((nf+2)/2) * W/nf * 0.18u'"
ps="'2*int((nf+2)/2) * (W/nf + 0.18u)'"
nrd="'0.18u / W'" nrs="'0.18u / W'"
sa=0 sb=0 sd=0
model=nfet_03v3
spiceprefix=X
}
C {devices/lab_pin.sym} 1015 -15 0 0 {name=p6 sig_type=std_logic lab=VSS}
C {devices/lab_pin.sym} 655 -570 0 0 {name=p7 sig_type=std_logic lab=VDD}
C {symbols/nfet_03v3.sym} 95 -175 0 0 {name=M21
L=0.5u
W=19.2u
nf=1
m=1
ad="'int((nf+1)/2) * W/nf * 0.18u'"
pd="'2*int((nf+1)/2) * (W/nf + 0.18u)'"
as="'int((nf+2)/2) * W/nf * 0.18u'"
ps="'2*int((nf+2)/2) * (W/nf + 0.18u)'"
nrd="'0.18u / W'" nrs="'0.18u / W'"
sa=0 sb=0 sd=0
model=nfet_03v3
spiceprefix=X
}
C {symbols/nfet_03v3.sym} 95 -75 0 0 {name=M22
L=0.5u
W=19.2u
nf=1
m=1
ad="'int((nf+1)/2) * W/nf * 0.18u'"
pd="'2*int((nf+1)/2) * (W/nf + 0.18u)'"
as="'int((nf+2)/2) * W/nf * 0.18u'"
ps="'2*int((nf+2)/2) * (W/nf + 0.18u)'"
nrd="'0.18u / W'" nrs="'0.18u / W'"
sa=0 sb=0 sd=0
model=nfet_03v3
spiceprefix=X
}
C {Balanced_Inverter.sym} 1875 -1295 0 1 {name=x1}
C {Balanced_Inverter.sym} 1625 -1295 0 1 {name=x2}
C {Balanced_Inverter.sym} 1405 -1295 0 1 {name=x3}
C {Balanced_Inverter.sym} 1155 -1295 0 1 {name=x4}
C {Balanced_Inverter.sym} 925 -1295 0 1 {name=x5}
C {Balanced_Inverter.sym} 675 -1295 0 1 {name=x6}
C {symbols/nfet_03v3.sym} 1930 -900 0 0 {name=M23
L=0.5u
W=0.3u
nf=1
m=1
ad="'int((nf+1)/2) * W/nf * 0.18u'"
pd="'2*int((nf+1)/2) * (W/nf + 0.18u)'"
as="'int((nf+2)/2) * W/nf * 0.18u'"
ps="'2*int((nf+2)/2) * (W/nf + 0.18u)'"
nrd="'0.18u / W'" nrs="'0.18u / W'"
sa=0 sb=0 sd=0
model=nfet_03v3
spiceprefix=X
}
C {devices/lab_pin.sym} 2055 -1295 0 1 {name=p8 sig_type=std_logic lab=B1}
C {devices/lab_pin.sym} 1795 -1295 0 1 {name=p9 sig_type=std_logic lab=B2}
C {devices/lab_pin.sym} 1565 -1295 0 1 {name=p10 sig_type=std_logic lab=B3}
C {devices/lab_pin.sym} 1325 -1295 0 1 {name=p11 sig_type=std_logic lab=B4}
C {devices/lab_pin.sym} 1085 -1295 0 1 {name=p13 sig_type=std_logic lab=B5}
C {devices/lab_pin.sym} 835 -1295 0 1 {name=p12 sig_type=std_logic lab=B6}
C {devices/lab_pin.sym} 1955 -1375 0 1 {name=p22 sig_type=std_logic lab=VDD}
C {devices/lab_pin.sym} 1955 -1215 0 1 {name=p23 sig_type=std_logic lab=VSS}
C {devices/lab_pin.sym} 2120 -850 0 0 {name=p51 sig_type=std_logic lab=VSS}
C {devices/lab_pin.sym} 1960 -850 0 0 {name=p52 sig_type=std_logic lab=VSS}
C {devices/lab_pin.sym} 1730 -850 0 0 {name=p53 sig_type=std_logic lab=VSS}
C {devices/lab_pin.sym} 1570 -860 0 0 {name=p54 sig_type=std_logic lab=VSS}
C {devices/lab_pin.sym} 1390 -850 0 0 {name=p55 sig_type=std_logic lab=VSS}
C {devices/lab_pin.sym} 1230 -855 0 0 {name=p56 sig_type=std_logic lab=VSS}
C {devices/lab_pin.sym} 620 -850 0 0 {name=p57 sig_type=std_logic lab=VSS}
C {devices/lab_pin.sym} 460 -840 0 0 {name=p58 sig_type=std_logic lab=VSS}
C {devices/lab_pin.sym} 230 -850 0 0 {name=p59 sig_type=std_logic lab=VSS}
C {devices/lab_pin.sym} 70 -840 0 0 {name=p60 sig_type=std_logic lab=VSS}
C {devices/lab_pin.sym} 840 -840 0 0 {name=p61 sig_type=std_logic lab=VSS}
C {devices/lab_pin.sym} 1000 -850 0 0 {name=p62 sig_type=std_logic lab=VSS}
C {devices/iopin.sym} 2260 -1160 0 0 {name=p66 lab=VDD}
C {devices/iopin.sym} 2260 -1130 0 0 {name=p67 lab=VSS}
C {devices/ipin.sym} 2310 -1100 0 0 {name=p68 lab=B1}
C {devices/ipin.sym} 2310 -1070 0 0 {name=p69 lab=B2}
C {devices/ipin.sym} 2310 -1040 0 0 {name=p70 lab=B3}
C {devices/ipin.sym} 2310 -1010 0 0 {name=p71 lab=B4}
C {devices/ipin.sym} 2310 -980 0 0 {name=p72 lab=B5}
C {devices/ipin.sym} 2310 -950 0 0 {name=p73 lab=B6}
C {devices/ipin.sym} 3220 -450 0 0 {name=p75 lab=ITAIL}
C {devices/opin.sym} -270 -1000 0 1 {name=p76 lab=OUT+}
C {devices/opin.sym} -365 -920 2 0 {name=p77 lab=OUT-}
C {symbols/nfet_03v3.sym} 2090 -900 0 0 {name=M24
L=0.5u
W=0.3u
nf=1
m=1
ad="'int((nf+1)/2) * W/nf * 0.18u'"
pd="'2*int((nf+1)/2) * (W/nf + 0.18u)'"
as="'int((nf+2)/2) * W/nf * 0.18u'"
ps="'2*int((nf+2)/2) * (W/nf + 0.18u)'"
nrd="'0.18u / W'" nrs="'0.18u / W'"
sa=0 sb=0 sd=0
model=nfet_03v3
spiceprefix=X
}
C {symbols/nfet_03v3.sym} 2090 -805 0 0 {name=M25
L=0.5u
W=0.6u
nf=1
m=1
ad="'int((nf+1)/2) * W/nf * 0.18u'"
pd="'2*int((nf+1)/2) * (W/nf + 0.18u)'"
as="'int((nf+2)/2) * W/nf * 0.18u'"
ps="'2*int((nf+2)/2) * (W/nf + 0.18u)'"
nrd="'0.18u / W'" nrs="'0.18u / W'"
sa=0 sb=0 sd=0
model=nfet_03v3
spiceprefix=X
}
C {symbols/nfet_03v3.sym} 1930 -805 0 0 {name=M26
L=0.5u
W=0.6u
nf=1
m=1
ad="'int((nf+1)/2) * W/nf * 0.18u'"
pd="'2*int((nf+1)/2) * (W/nf + 0.18u)'"
as="'int((nf+2)/2) * W/nf * 0.18u'"
ps="'2*int((nf+2)/2) * (W/nf + 0.18u)'"
nrd="'0.18u / W'" nrs="'0.18u / W'"
sa=0 sb=0 sd=0
model=nfet_03v3
spiceprefix=X
}
C {symbols/nfet_03v3.sym} 1700 -900 0 0 {name=M27
L=0.5u
W=0.6u
nf=1
m=1
ad="'int((nf+1)/2) * W/nf * 0.18u'"
pd="'2*int((nf+1)/2) * (W/nf + 0.18u)'"
as="'int((nf+2)/2) * W/nf * 0.18u'"
ps="'2*int((nf+2)/2) * (W/nf + 0.18u)'"
nrd="'0.18u / W'" nrs="'0.18u / W'"
sa=0 sb=0 sd=0
model=nfet_03v3
spiceprefix=X
}
C {symbols/nfet_03v3.sym} 1540 -900 0 0 {name=M28
L=0.5u
W=0.6u
nf=1
m=1
ad="'int((nf+1)/2) * W/nf * 0.18u'"
pd="'2*int((nf+1)/2) * (W/nf + 0.18u)'"
as="'int((nf+2)/2) * W/nf * 0.18u'"
ps="'2*int((nf+2)/2) * (W/nf + 0.18u)'"
nrd="'0.18u / W'" nrs="'0.18u / W'"
sa=0 sb=0 sd=0
model=nfet_03v3
spiceprefix=X
}
C {symbols/nfet_03v3.sym} 1700 -805 0 0 {name=M29
L=0.5u
W=1.2u
nf=1
m=1
ad="'int((nf+1)/2) * W/nf * 0.18u'"
pd="'2*int((nf+1)/2) * (W/nf + 0.18u)'"
as="'int((nf+2)/2) * W/nf * 0.18u'"
ps="'2*int((nf+2)/2) * (W/nf + 0.18u)'"
nrd="'0.18u / W'" nrs="'0.18u / W'"
sa=0 sb=0 sd=0
model=nfet_03v3
spiceprefix=X
}
C {symbols/nfet_03v3.sym} 1540 -800 0 0 {name=M30
L=0.5u
W=1.2u
nf=1
m=1
ad="'int((nf+1)/2) * W/nf * 0.18u'"
pd="'2*int((nf+1)/2) * (W/nf + 0.18u)'"
as="'int((nf+2)/2) * W/nf * 0.18u'"
ps="'2*int((nf+2)/2) * (W/nf + 0.18u)'"
nrd="'0.18u / W'" nrs="'0.18u / W'"
sa=0 sb=0 sd=0
model=nfet_03v3
spiceprefix=X
}
C {symbols/nfet_03v3.sym} 1360 -900 0 0 {name=M31
L=0.5u
W=1.2u
nf=1
m=1
ad="'int((nf+1)/2) * W/nf * 0.18u'"
pd="'2*int((nf+1)/2) * (W/nf + 0.18u)'"
as="'int((nf+2)/2) * W/nf * 0.18u'"
ps="'2*int((nf+2)/2) * (W/nf + 0.18u)'"
nrd="'0.18u / W'" nrs="'0.18u / W'"
sa=0 sb=0 sd=0
model=nfet_03v3
spiceprefix=X
}
C {symbols/nfet_03v3.sym} 1200 -900 0 0 {name=M32
L=0.5u
W=1.2u
nf=1
m=1
ad="'int((nf+1)/2) * W/nf * 0.18u'"
pd="'2*int((nf+1)/2) * (W/nf + 0.18u)'"
as="'int((nf+2)/2) * W/nf * 0.18u'"
ps="'2*int((nf+2)/2) * (W/nf + 0.18u)'"
nrd="'0.18u / W'" nrs="'0.18u / W'"
sa=0 sb=0 sd=0
model=nfet_03v3
spiceprefix=X
}
C {symbols/nfet_03v3.sym} 40 -900 0 0 {name=M33
L=0.5u
W=9.6u
nf=1
m=1
ad="'int((nf+1)/2) * W/nf * 0.18u'"
pd="'2*int((nf+1)/2) * (W/nf + 0.18u)'"
as="'int((nf+2)/2) * W/nf * 0.18u'"
ps="'2*int((nf+2)/2) * (W/nf + 0.18u)'"
nrd="'0.18u / W'" nrs="'0.18u / W'"
sa=0 sb=0 sd=0
model=nfet_03v3
spiceprefix=X
}
C {symbols/nfet_03v3.sym} 40 -795 0 0 {name=M34
L=0.5u
W=19.2u
nf=1
m=1
ad="'int((nf+1)/2) * W/nf * 0.18u'"
pd="'2*int((nf+1)/2) * (W/nf + 0.18u)'"
as="'int((nf+2)/2) * W/nf * 0.18u'"
ps="'2*int((nf+2)/2) * (W/nf + 0.18u)'"
nrd="'0.18u / W'" nrs="'0.18u / W'"
sa=0 sb=0 sd=0
model=nfet_03v3
spiceprefix=X
}
C {symbols/nfet_03v3.sym} 200 -900 0 0 {name=M35
L=0.5u
W=9.6u
nf=1
m=1
ad="'int((nf+1)/2) * W/nf * 0.18u'"
pd="'2*int((nf+1)/2) * (W/nf + 0.18u)'"
as="'int((nf+2)/2) * W/nf * 0.18u'"
ps="'2*int((nf+2)/2) * (W/nf + 0.18u)'"
nrd="'0.18u / W'" nrs="'0.18u / W'"
sa=0 sb=0 sd=0
model=nfet_03v3
spiceprefix=X
}
C {symbols/nfet_03v3.sym} 200 -800 0 0 {name=M36
L=0.5u
W=19.2u
nf=1
m=1
ad="'int((nf+1)/2) * W/nf * 0.18u'"
pd="'2*int((nf+1)/2) * (W/nf + 0.18u)'"
as="'int((nf+2)/2) * W/nf * 0.18u'"
ps="'2*int((nf+2)/2) * (W/nf + 0.18u)'"
nrd="'0.18u / W'" nrs="'0.18u / W'"
sa=0 sb=0 sd=0
model=nfet_03v3
spiceprefix=X
}
C {symbols/nfet_03v3.sym} 430 -900 0 0 {name=M37
L=0.5u
W=4.8u
nf=1
m=1
ad="'int((nf+1)/2) * W/nf * 0.18u'"
pd="'2*int((nf+1)/2) * (W/nf + 0.18u)'"
as="'int((nf+2)/2) * W/nf * 0.18u'"
ps="'2*int((nf+2)/2) * (W/nf + 0.18u)'"
nrd="'0.18u / W'" nrs="'0.18u / W'"
sa=0 sb=0 sd=0
model=nfet_03v3
spiceprefix=X
}
C {symbols/nfet_03v3.sym} 590 -900 0 0 {name=M38
L=0.5u
W=4.8u
nf=1
m=1
ad="'int((nf+1)/2) * W/nf * 0.18u'"
pd="'2*int((nf+1)/2) * (W/nf + 0.18u)'"
as="'int((nf+2)/2) * W/nf * 0.18u'"
ps="'2*int((nf+2)/2) * (W/nf + 0.18u)'"
nrd="'0.18u / W'" nrs="'0.18u / W'"
sa=0 sb=0 sd=0
model=nfet_03v3
spiceprefix=X
}
C {symbols/nfet_03v3.sym} 810 -900 0 0 {name=M39
L=0.5u
W=2.4u
nf=1
m=1
ad="'int((nf+1)/2) * W/nf * 0.18u'"
pd="'2*int((nf+1)/2) * (W/nf + 0.18u)'"
as="'int((nf+2)/2) * W/nf * 0.18u'"
ps="'2*int((nf+2)/2) * (W/nf + 0.18u)'"
nrd="'0.18u / W'" nrs="'0.18u / W'"
sa=0 sb=0 sd=0
model=nfet_03v3
spiceprefix=X
}
C {symbols/nfet_03v3.sym} 430 -795 0 0 {name=M40
L=0.5u
W=9.6u
nf=1
m=1
ad="'int((nf+1)/2) * W/nf * 0.18u'"
pd="'2*int((nf+1)/2) * (W/nf + 0.18u)'"
as="'int((nf+2)/2) * W/nf * 0.18u'"
ps="'2*int((nf+2)/2) * (W/nf + 0.18u)'"
nrd="'0.18u / W'" nrs="'0.18u / W'"
sa=0 sb=0 sd=0
model=nfet_03v3
spiceprefix=X
}
C {symbols/nfet_03v3.sym} 590 -795 0 0 {name=M41
L=0.5u
W=9.6u
nf=1
m=1
ad="'int((nf+1)/2) * W/nf * 0.18u'"
pd="'2*int((nf+1)/2) * (W/nf + 0.18u)'"
as="'int((nf+2)/2) * W/nf * 0.18u'"
ps="'2*int((nf+2)/2) * (W/nf + 0.18u)'"
nrd="'0.18u / W'" nrs="'0.18u / W'"
sa=0 sb=0 sd=0
model=nfet_03v3
spiceprefix=X
}
C {symbols/nfet_03v3.sym} 810 -795 0 0 {name=M42
L=0.5u
W=4.8u
nf=1
m=1
ad="'int((nf+1)/2) * W/nf * 0.18u'"
pd="'2*int((nf+1)/2) * (W/nf + 0.18u)'"
as="'int((nf+2)/2) * W/nf * 0.18u'"
ps="'2*int((nf+2)/2) * (W/nf + 0.18u)'"
nrd="'0.18u / W'" nrs="'0.18u / W'"
sa=0 sb=0 sd=0
model=nfet_03v3
spiceprefix=X
}
C {symbols/nfet_03v3.sym} 970 -900 0 0 {name=M43
L=0.5u
W=2.4u
nf=1
m=1
ad="'int((nf+1)/2) * W/nf * 0.18u'"
pd="'2*int((nf+1)/2) * (W/nf + 0.18u)'"
as="'int((nf+2)/2) * W/nf * 0.18u'"
ps="'2*int((nf+2)/2) * (W/nf + 0.18u)'"
nrd="'0.18u / W'" nrs="'0.18u / W'"
sa=0 sb=0 sd=0
model=nfet_03v3
spiceprefix=X
}
C {symbols/nfet_03v3.sym} 970 -795 0 0 {name=M44
L=0.5u
W=4.8u
nf=1
m=1
ad="'int((nf+1)/2) * W/nf * 0.18u'"
pd="'2*int((nf+1)/2) * (W/nf + 0.18u)'"
as="'int((nf+2)/2) * W/nf * 0.18u'"
ps="'2*int((nf+2)/2) * (W/nf + 0.18u)'"
nrd="'0.18u / W'" nrs="'0.18u / W'"
sa=0 sb=0 sd=0
model=nfet_03v3
spiceprefix=X
}
C {symbols/nfet_03v3.sym} 1200 -800 0 0 {name=M45
L=0.5u
W=2.4u
nf=1
m=1
ad="'int((nf+1)/2) * W/nf * 0.18u'"
pd="'2*int((nf+1)/2) * (W/nf + 0.18u)'"
as="'int((nf+2)/2) * W/nf * 0.18u'"
ps="'2*int((nf+2)/2) * (W/nf + 0.18u)'"
nrd="'0.18u / W'" nrs="'0.18u / W'"
sa=0 sb=0 sd=0
model=nfet_03v3
spiceprefix=X
}
C {symbols/nfet_03v3.sym} 1360 -800 0 0 {name=M46
L=0.5u
W=2.4u
nf=1
m=1
ad="'int((nf+1)/2) * W/nf * 0.18u'"
pd="'2*int((nf+1)/2) * (W/nf + 0.18u)'"
as="'int((nf+2)/2) * W/nf * 0.18u'"
ps="'2*int((nf+2)/2) * (W/nf + 0.18u)'"
nrd="'0.18u / W'" nrs="'0.18u / W'"
sa=0 sb=0 sd=0
model=nfet_03v3
spiceprefix=X
}
C {symbols/nfet_03v3.sym} 2160 -980 0 0 {name=M47
L=0.5u
W=0.3u
nf=1
m=1
ad="'int((nf+1)/2) * W/nf * 0.18u'"
pd="'2*int((nf+1)/2) * (W/nf + 0.18u)'"
as="'int((nf+2)/2) * W/nf * 0.18u'"
ps="'2*int((nf+2)/2) * (W/nf + 0.18u)'"
nrd="'0.18u / W'" nrs="'0.18u / W'"
sa=0 sb=0 sd=0
model=nfet_03v3
spiceprefix=X
}
C {devices/lab_pin.sym} 2230 -980 0 0 {name=p25 sig_type=std_logic lab=VSS}
C {symbols/nfet_03v3.sym} 2080 -695 0 0 {name=M48
L=0.5u
W=0.6u
nf=1
m=1
ad="'int((nf+1)/2) * W/nf * 0.18u'"
pd="'2*int((nf+1)/2) * (W/nf + 0.18u)'"
as="'int((nf+2)/2) * W/nf * 0.18u'"
ps="'2*int((nf+2)/2) * (W/nf + 0.18u)'"
nrd="'0.18u / W'" nrs="'0.18u / W'"
sa=0 sb=0 sd=0
model=nfet_03v3
spiceprefix=X
}
C {devices/lab_pin.sym} 2135 -695 0 1 {name=p26 sig_type=std_logic lab=VSS}
C {symbols/nfet_03v3.sym} 1670 -745 0 0 {name=M49
L=0.5u
W=1.8u
nf=1
m=1
ad="'int((nf+1)/2) * W/nf * 0.18u'"
pd="'2*int((nf+1)/2) * (W/nf + 0.18u)'"
as="'int((nf+2)/2) * W/nf * 0.18u'"
ps="'2*int((nf+2)/2) * (W/nf + 0.18u)'"
nrd="'0.18u / W'" nrs="'0.18u / W'"
sa=0 sb=0 sd=0
model=nfet_03v3
spiceprefix=X
}
C {devices/lab_pin.sym} 1725 -745 0 1 {name=p27 sig_type=std_logic lab=VSS}
C {symbols/nfet_03v3.sym} 1290 -755 0 0 {name=M50
L=0.5u
W=1.2u
nf=1
m=1
ad="'int((nf+1)/2) * W/nf * 0.18u'"
pd="'2*int((nf+1)/2) * (W/nf + 0.18u)'"
as="'int((nf+2)/2) * W/nf * 0.18u'"
ps="'2*int((nf+2)/2) * (W/nf + 0.18u)'"
nrd="'0.18u / W'" nrs="'0.18u / W'"
sa=0 sb=0 sd=0
model=nfet_03v3
spiceprefix=X
}
C {symbols/nfet_03v3.sym} 1990 -1030 0 0 {name=M51
L=0.5u
W=0.6u
nf=1
m=1
ad="'int((nf+1)/2) * W/nf * 0.18u'"
pd="'2*int((nf+1)/2) * (W/nf + 0.18u)'"
as="'int((nf+2)/2) * W/nf * 0.18u'"
ps="'2*int((nf+2)/2) * (W/nf + 0.18u)'"
nrd="'0.18u / W'" nrs="'0.18u / W'"
sa=0 sb=0 sd=0
model=nfet_03v3
spiceprefix=X
}
C {symbols/nfet_03v3.sym} 2215 -795 0 0 {name=M52
L=0.5u
W=1.8u
nf=1
m=1
ad="'int((nf+1)/2) * W/nf * 0.18u'"
pd="'2*int((nf+1)/2) * (W/nf + 0.18u)'"
as="'int((nf+2)/2) * W/nf * 0.18u'"
ps="'2*int((nf+2)/2) * (W/nf + 0.18u)'"
nrd="'0.18u / W'" nrs="'0.18u / W'"
sa=0 sb=0 sd=0
model=nfet_03v3
spiceprefix=X
}
C {devices/lab_pin.sym} 2270 -795 0 1 {name=p28 sig_type=std_logic lab=VSS}
C {devices/lab_pin.sym} 1345 -755 0 1 {name=p29 sig_type=std_logic lab=VSS}
C {symbols/nfet_03v3.sym} 1045 -835 0 0 {name=M53
L=0.5u
W=2.4u
nf=1
m=1
ad="'int((nf+1)/2) * W/nf * 0.18u'"
pd="'2*int((nf+1)/2) * (W/nf + 0.18u)'"
as="'int((nf+2)/2) * W/nf * 0.18u'"
ps="'2*int((nf+2)/2) * (W/nf + 0.18u)'"
nrd="'0.18u / W'" nrs="'0.18u / W'"
sa=0 sb=0 sd=0
model=nfet_03v3
spiceprefix=X
}
C {devices/lab_pin.sym} 1100 -835 0 1 {name=p78 sig_type=std_logic lab=VSS}
C {symbols/nfet_03v3.sym} 910 -750 0 0 {name=M54
L=0.5u
W=2.4u
nf=1
m=1
ad="'int((nf+1)/2) * W/nf * 0.18u'"
pd="'2*int((nf+1)/2) * (W/nf + 0.18u)'"
as="'int((nf+2)/2) * W/nf * 0.18u'"
ps="'2*int((nf+2)/2) * (W/nf + 0.18u)'"
nrd="'0.18u / W'" nrs="'0.18u / W'"
sa=0 sb=0 sd=0
model=nfet_03v3
spiceprefix=X
}
C {devices/lab_pin.sym} 965 -750 0 1 {name=p79 sig_type=std_logic lab=VSS}
C {symbols/nfet_03v3.sym} 520 -750 0 0 {name=M55
L=0.5u
W=4.8u
nf=1
m=1
ad="'int((nf+1)/2) * W/nf * 0.18u'"
pd="'2*int((nf+1)/2) * (W/nf + 0.18u)'"
as="'int((nf+2)/2) * W/nf * 0.18u'"
ps="'2*int((nf+2)/2) * (W/nf + 0.18u)'"
nrd="'0.18u / W'" nrs="'0.18u / W'"
sa=0 sb=0 sd=0
model=nfet_03v3
spiceprefix=X
}
C {devices/lab_pin.sym} 575 -750 0 1 {name=p80 sig_type=std_logic lab=VSS}
C {symbols/nfet_03v3.sym} 660 -825 0 0 {name=M56
L=0.5u
W=4.8u
nf=1
m=1
ad="'int((nf+1)/2) * W/nf * 0.18u'"
pd="'2*int((nf+1)/2) * (W/nf + 0.18u)'"
as="'int((nf+2)/2) * W/nf * 0.18u'"
ps="'2*int((nf+2)/2) * (W/nf + 0.18u)'"
nrd="'0.18u / W'" nrs="'0.18u / W'"
sa=0 sb=0 sd=0
model=nfet_03v3
spiceprefix=X
}
C {devices/lab_pin.sym} 715 -825 0 1 {name=p81 sig_type=std_logic lab=VSS}
C {symbols/nfet_03v3.sym} 270 -830 0 0 {name=M57
L=0.5u
W=9.6u
nf=1
m=1
ad="'int((nf+1)/2) * W/nf * 0.18u'"
pd="'2*int((nf+1)/2) * (W/nf + 0.18u)'"
as="'int((nf+2)/2) * W/nf * 0.18u'"
ps="'2*int((nf+2)/2) * (W/nf + 0.18u)'"
nrd="'0.18u / W'" nrs="'0.18u / W'"
sa=0 sb=0 sd=0
model=nfet_03v3
spiceprefix=X
}
C {devices/lab_pin.sym} 325 -830 0 1 {name=p82 sig_type=std_logic lab=VSS}
C {symbols/nfet_03v3.sym} -110 -850 0 0 {name=M58
L=0.5u
W=9.6u
nf=1
m=1
ad="'int((nf+1)/2) * W/nf * 0.18u'"
pd="'2*int((nf+1)/2) * (W/nf + 0.18u)'"
as="'int((nf+2)/2) * W/nf * 0.18u'"
ps="'2*int((nf+2)/2) * (W/nf + 0.18u)'"
nrd="'0.18u / W'" nrs="'0.18u / W'"
sa=0 sb=0 sd=0
model=nfet_03v3
spiceprefix=X
}
C {devices/lab_pin.sym} -55 -850 0 1 {name=p83 sig_type=std_logic lab=VSS}
C {devices/lab_pin.sym} 2060 -1030 0 1 {name=p19 sig_type=std_logic lab=VSS}
C {symbols/nfet_03v3.sym} 1740 -1050 0 0 {name=M59
L=0.5u
W=0.3u
nf=1
m=1
ad="'int((nf+1)/2) * W/nf * 0.18u'"
pd="'2*int((nf+1)/2) * (W/nf + 0.18u)'"
as="'int((nf+2)/2) * W/nf * 0.18u'"
ps="'2*int((nf+2)/2) * (W/nf + 0.18u)'"
nrd="'0.18u / W'" nrs="'0.18u / W'"
sa=0 sb=0 sd=0
model=nfet_03v3
spiceprefix=X
}
C {devices/lab_pin.sym} 1810 -1050 0 0 {name=p20 sig_type=std_logic lab=VSS}
C {symbols/nfet_03v3.sym} 1390 -1050 0 0 {name=M60
L=0.5u
W=0.6u
nf=1
m=1
ad="'int((nf+1)/2) * W/nf * 0.18u'"
pd="'2*int((nf+1)/2) * (W/nf + 0.18u)'"
as="'int((nf+2)/2) * W/nf * 0.18u'"
ps="'2*int((nf+2)/2) * (W/nf + 0.18u)'"
nrd="'0.18u / W'" nrs="'0.18u / W'"
sa=0 sb=0 sd=0
model=nfet_03v3
spiceprefix=X
}
C {devices/lab_pin.sym} 1460 -1050 0 0 {name=p21 sig_type=std_logic lab=VSS}
C {symbols/nfet_03v3.sym} 890 -1050 0 0 {name=M61
L=0.5u
W=0.6u
nf=1
m=1
ad="'int((nf+1)/2) * W/nf * 0.18u'"
pd="'2*int((nf+1)/2) * (W/nf + 0.18u)'"
as="'int((nf+2)/2) * W/nf * 0.18u'"
ps="'2*int((nf+2)/2) * (W/nf + 0.18u)'"
nrd="'0.18u / W'" nrs="'0.18u / W'"
sa=0 sb=0 sd=0
model=nfet_03v3
spiceprefix=X
}
C {devices/lab_pin.sym} 960 -1050 0 0 {name=p42 sig_type=std_logic lab=VSS}
C {symbols/nfet_03v3.sym} 1060 -1060 0 0 {name=M62
L=0.5u
W=0.6u
nf=1
m=1
ad="'int((nf+1)/2) * W/nf * 0.18u'"
pd="'2*int((nf+1)/2) * (W/nf + 0.18u)'"
as="'int((nf+2)/2) * W/nf * 0.18u'"
ps="'2*int((nf+2)/2) * (W/nf + 0.18u)'"
nrd="'0.18u / W'" nrs="'0.18u / W'"
sa=0 sb=0 sd=0
model=nfet_03v3
spiceprefix=X
}
C {devices/lab_pin.sym} 1130 -1060 0 0 {name=p43 sig_type=std_logic lab=VSS}
C {symbols/nfet_03v3.sym} 500 -1040 0 0 {name=M63
L=0.5u
W=2.4u
nf=1
m=1
ad="'int((nf+1)/2) * W/nf * 0.18u'"
pd="'2*int((nf+1)/2) * (W/nf + 0.18u)'"
as="'int((nf+2)/2) * W/nf * 0.18u'"
ps="'2*int((nf+2)/2) * (W/nf + 0.18u)'"
nrd="'0.18u / W'" nrs="'0.18u / W'"
sa=0 sb=0 sd=0
model=nfet_03v3
spiceprefix=X
}
C {devices/lab_pin.sym} 570 -1040 0 0 {name=p44 sig_type=std_logic lab=VSS}
C {symbols/nfet_03v3.sym} 110 -1040 0 0 {name=M64
L=0.5u
W=2.4u
nf=1
m=1
ad="'int((nf+1)/2) * W/nf * 0.18u'"
pd="'2*int((nf+1)/2) * (W/nf + 0.18u)'"
as="'int((nf+2)/2) * W/nf * 0.18u'"
ps="'2*int((nf+2)/2) * (W/nf + 0.18u)'"
nrd="'0.18u / W'" nrs="'0.18u / W'"
sa=0 sb=0 sd=0
model=nfet_03v3
spiceprefix=X
}
C {devices/lab_pin.sym} 180 -1040 0 0 {name=p45 sig_type=std_logic lab=VSS}
C {symbols/nfet_03v3.sym} 290 -1000 0 0 {name=M65
L=0.5u
W=2.4u
nf=1
m=1
ad="'int((nf+1)/2) * W/nf * 0.18u'"
pd="'2*int((nf+1)/2) * (W/nf + 0.18u)'"
as="'int((nf+2)/2) * W/nf * 0.18u'"
ps="'2*int((nf+2)/2) * (W/nf + 0.18u)'"
nrd="'0.18u / W'" nrs="'0.18u / W'"
sa=0 sb=0 sd=0
model=nfet_03v3
spiceprefix=X
}
C {devices/lab_pin.sym} 360 -1000 0 0 {name=p46 sig_type=std_logic lab=VSS}
C {devices/lab_pin.sym} 1835 -1155 0 0 {name=p1 sig_type=std_logic lab=b1}
C {devices/lab_pin.sym} 1910 -1150 0 0 {name=p2 sig_type=std_logic lab=b1b}
C {devices/lab_pin.sym} 1480 -1145 0 0 {name=p3 sig_type=std_logic lab=b2}
C {devices/lab_pin.sym} 1520 -1135 0 0 {name=p4 sig_type=std_logic lab=b2b}
C {devices/lab_pin.sym} 1320 -1140 0 0 {name=p5 sig_type=std_logic lab=b3}
C {devices/lab_pin.sym} 1305 -1170 0 0 {name=p14 sig_type=std_logic lab=b3b}
C {devices/lab_pin.sym} 1115 -1200 0 0 {name=p15 sig_type=std_logic lab=b4}
C {devices/lab_pin.sym} 1020 -1195 0 0 {name=p16 sig_type=std_logic lab=b4b}
C {devices/lab_pin.sym} 885 -1205 0 0 {name=p17 sig_type=std_logic lab=b5}
C {devices/lab_pin.sym} 760 -1190 0 0 {name=p18 sig_type=std_logic lab=b5b}
C {devices/lab_pin.sym} 635 -1245 0 0 {name=p24 sig_type=std_logic lab=b6}
C {devices/lab_pin.sym} 440 -1345 0 0 {name=p30 sig_type=std_logic lab=b6b}
C {TG.sym} -150 -1000 0 1 {name=x7}
C {TG.sym} -250 -920 0 1 {name=x8}
C {devices/lab_pin.sym} -180 -870 0 0 {name=p31 sig_type=std_logic lab=VSS}
C {devices/lab_pin.sym} -170 -1060 0 0 {name=p32 sig_type=std_logic lab=VDD}
C {devices/ipin.sym} -70 -1010 1 0 {name=p33 lab=SEL_L}
C {CM_32_s.sym} -90 -165 0 1 {name=x9}
C {devices/lab_pin.sym} -100 -260 0 0 {name=p34 sig_type=std_logic lab=VDD}
C {devices/lab_pin.sym} -70 -75 0 0 {name=p35 sig_type=std_logic lab=VSS}
C {devices/opin.sym} -230 -175 0 1 {name=p36 lab=G3_2}
C {devices/opin.sym} -230 -155 0 1 {name=p37 lab=G3_1}
C {symbols/nfet_03v3.sym} 2955 -295 0 0 {name=M66
L=0.5u
W=20u
nf=1
m=1
ad="'int((nf+1)/2) * W/nf * 0.18u'"
pd="'2*int((nf+1)/2) * (W/nf + 0.18u)'"
as="'int((nf+2)/2) * W/nf * 0.18u'"
ps="'2*int((nf+2)/2) * (W/nf + 0.18u)'"
nrd="'0.18u / W'" nrs="'0.18u / W'"
sa=0 sb=0 sd=0
model=nfet_03v3
spiceprefix=X
}
C {symbols/nfet_03v3.sym} 2955 -195 0 0 {name=M67
L=0.5u
W=20u
nf=1
m=1
ad="'int((nf+1)/2) * W/nf * 0.18u'"
pd="'2*int((nf+1)/2) * (W/nf + 0.18u)'"
as="'int((nf+2)/2) * W/nf * 0.18u'"
ps="'2*int((nf+2)/2) * (W/nf + 0.18u)'"
nrd="'0.18u / W'" nrs="'0.18u / W'"
sa=0 sb=0 sd=0
model=nfet_03v3
spiceprefix=X
}
C {symbols/pfet_03v3.sym} 2955 -530 0 0 {name=M68
L=0.5u
W=20u
nf=1
m=1
ad="'int((nf+1)/2) * W/nf * 0.18u'"
pd="'2*int((nf+1)/2) * (W/nf + 0.18u)'"
as="'int((nf+2)/2) * W/nf * 0.18u'"
ps="'2*int((nf+2)/2) * (W/nf + 0.18u)'"
nrd="'0.18u / W'" nrs="'0.18u / W'"
sa=0 sb=0 sd=0
model=pfet_03v3
spiceprefix=X
}
C {symbols/pfet_03v3.sym} 2955 -610 0 0 {name=M69
L=0.5u
W=20u
nf=1
m=1
ad="'int((nf+1)/2) * W/nf * 0.18u'"
pd="'2*int((nf+1)/2) * (W/nf + 0.18u)'"
as="'int((nf+2)/2) * W/nf * 0.18u'"
ps="'2*int((nf+2)/2) * (W/nf + 0.18u)'"
nrd="'0.18u / W'" nrs="'0.18u / W'"
sa=0 sb=0 sd=0
model=pfet_03v3
spiceprefix=X
}
C {symbols/pfet_03v3.sym} 2770 -530 0 1 {name=M70
L=0.5u
W=4u
nf=1
m=1
ad="'int((nf+1)/2) * W/nf * 0.18u'"
pd="'2*int((nf+1)/2) * (W/nf + 0.18u)'"
as="'int((nf+2)/2) * W/nf * 0.18u'"
ps="'2*int((nf+2)/2) * (W/nf + 0.18u)'"
nrd="'0.18u / W'" nrs="'0.18u / W'"
sa=0 sb=0 sd=0
model=pfet_03v3
spiceprefix=X
}
C {symbols/pfet_03v3.sym} 2770 -610 0 1 {name=M71
L=0.5u
W=4u
nf=1
m=1
ad="'int((nf+1)/2) * W/nf * 0.18u'"
pd="'2*int((nf+1)/2) * (W/nf + 0.18u)'"
as="'int((nf+2)/2) * W/nf * 0.18u'"
ps="'2*int((nf+2)/2) * (W/nf + 0.18u)'"
nrd="'0.18u / W'" nrs="'0.18u / W'"
sa=0 sb=0 sd=0
model=pfet_03v3
spiceprefix=X
}
C {symbols/nfet_03v3.sym} 2730 -295 0 0 {name=M72
L=0.5u
W=4.8u
nf=1
m=1
ad="'int((nf+1)/2) * W/nf * 0.18u'"
pd="'2*int((nf+1)/2) * (W/nf + 0.18u)'"
as="'int((nf+2)/2) * W/nf * 0.18u'"
ps="'2*int((nf+2)/2) * (W/nf + 0.18u)'"
nrd="'0.18u / W'" nrs="'0.18u / W'"
sa=0 sb=0 sd=0
model=nfet_03v3
spiceprefix=X
}
C {symbols/nfet_03v3.sym} 2730 -195 0 0 {name=M73
L=0.5u
W=4.8u
nf=1
m=1
ad="'int((nf+1)/2) * W/nf * 0.18u'"
pd="'2*int((nf+1)/2) * (W/nf + 0.18u)'"
as="'int((nf+2)/2) * W/nf * 0.18u'"
ps="'2*int((nf+2)/2) * (W/nf + 0.18u)'"
nrd="'0.18u / W'" nrs="'0.18u / W'"
sa=0 sb=0 sd=0
model=nfet_03v3
spiceprefix=X
}
C {devices/opin.sym} 2480 -590 0 0 {name=p41 lab=G_source_up}
C {symbols/nfet_03v3.sym} 3200 -295 0 0 {name=M74
L=0.5u
W=20u
nf=1
m=1
ad="'int((nf+1)/2) * W/nf * 0.18u'"
pd="'2*int((nf+1)/2) * (W/nf + 0.18u)'"
as="'int((nf+2)/2) * W/nf * 0.18u'"
ps="'2*int((nf+2)/2) * (W/nf + 0.18u)'"
nrd="'0.18u / W'" nrs="'0.18u / W'"
sa=0 sb=0 sd=0
model=nfet_03v3
spiceprefix=X
}
C {symbols/nfet_03v3.sym} 3200 -195 0 0 {name=M75
L=0.5u
W=20u
nf=1
m=1
ad="'int((nf+1)/2) * W/nf * 0.18u'"
pd="'2*int((nf+1)/2) * (W/nf + 0.18u)'"
as="'int((nf+2)/2) * W/nf * 0.18u'"
ps="'2*int((nf+2)/2) * (W/nf + 0.18u)'"
nrd="'0.18u / W'" nrs="'0.18u / W'"
sa=0 sb=0 sd=0
model=nfet_03v3
spiceprefix=X
}
C {symbols/nfet_03v3.sym} 2535 -295 0 0 {name=M76
L=0.5u
W=4.8u
nf=1
m=1
ad="'int((nf+1)/2) * W/nf * 0.18u'"
pd="'2*int((nf+1)/2) * (W/nf + 0.18u)'"
as="'int((nf+2)/2) * W/nf * 0.18u'"
ps="'2*int((nf+2)/2) * (W/nf + 0.18u)'"
nrd="'0.18u / W'" nrs="'0.18u / W'"
sa=0 sb=0 sd=0
model=nfet_03v3
spiceprefix=X
}
C {symbols/nfet_03v3.sym} 2535 -195 0 0 {name=M77
L=0.5u
W=4.8u
nf=1
m=1
ad="'int((nf+1)/2) * W/nf * 0.18u'"
pd="'2*int((nf+1)/2) * (W/nf + 0.18u)'"
as="'int((nf+2)/2) * W/nf * 0.18u'"
ps="'2*int((nf+2)/2) * (W/nf + 0.18u)'"
nrd="'0.18u / W'" nrs="'0.18u / W'"
sa=0 sb=0 sd=0
model=nfet_03v3
spiceprefix=X
}
C {symbols/pfet_03v3.sym} 2535 -530 0 0 {name=M78
L=0.5u
W=4.8u
nf=1
m=1
ad="'int((nf+1)/2) * W/nf * 0.18u'"
pd="'2*int((nf+1)/2) * (W/nf + 0.18u)'"
as="'int((nf+2)/2) * W/nf * 0.18u'"
ps="'2*int((nf+2)/2) * (W/nf + 0.18u)'"
nrd="'0.18u / W'" nrs="'0.18u / W'"
sa=0 sb=0 sd=0
model=pfet_03v3
spiceprefix=X
}
C {devices/opin.sym} 2480 -500 0 0 {name=p47 lab=G_source_dn}
C {devices/opin.sym} 2685 -345 0 0 {name=p48 lab=G_sink_up}
C {devices/opin.sym} 2685 -245 0 0 {name=p49 lab=G_sink_dn}
C {symbols/pfet_03v3.sym} 2535 -610 0 0 {name=M79
L=0.5u
W=4.8u
nf=1
m=1
ad="'int((nf+1)/2) * W/nf * 0.18u'"
pd="'2*int((nf+1)/2) * (W/nf + 0.18u)'"
as="'int((nf+2)/2) * W/nf * 0.18u'"
ps="'2*int((nf+2)/2) * (W/nf + 0.18u)'"
nrd="'0.18u / W'" nrs="'0.18u / W'"
sa=0 sb=0 sd=0
model=pfet_03v3
spiceprefix=X
}
C {symbols/pfet_03v3.sym} 2365 -605 0 1 {name=M80
L=0.5u
W=0.6u
nf=1
m=1
ad="'int((nf+1)/2) * W/nf * 0.18u'"
pd="'2*int((nf+1)/2) * (W/nf + 0.18u)'"
as="'int((nf+2)/2) * W/nf * 0.18u'"
ps="'2*int((nf+2)/2) * (W/nf + 0.18u)'"
nrd="'0.18u / W'" nrs="'0.18u / W'"
sa=0 sb=0 sd=0
model=pfet_03v3
spiceprefix=X
}
C {symbols/pfet_03v3.sym} 2365 -515 0 1 {name=M81
L=0.5u
W=0.6u
nf=1
m=1
ad="'int((nf+1)/2) * W/nf * 0.18u'"
pd="'2*int((nf+1)/2) * (W/nf + 0.18u)'"
as="'int((nf+2)/2) * W/nf * 0.18u'"
ps="'2*int((nf+2)/2) * (W/nf + 0.18u)'"
nrd="'0.18u / W'" nrs="'0.18u / W'"
sa=0 sb=0 sd=0
model=pfet_03v3
spiceprefix=X
}
C {devices/lab_pin.sym} 2910 -660 0 0 {name=p38 sig_type=std_logic lab=VDD}
C {devices/lab_pin.sym} 2880 -135 0 0 {name=p39 sig_type=std_logic lab=VDD}
